VERSION 5.7 ;
  NOWIREEXTENSIONATPIN ON ;
  DIVIDERCHAR "/" ;
  BUSBITCHARS "[]" ;
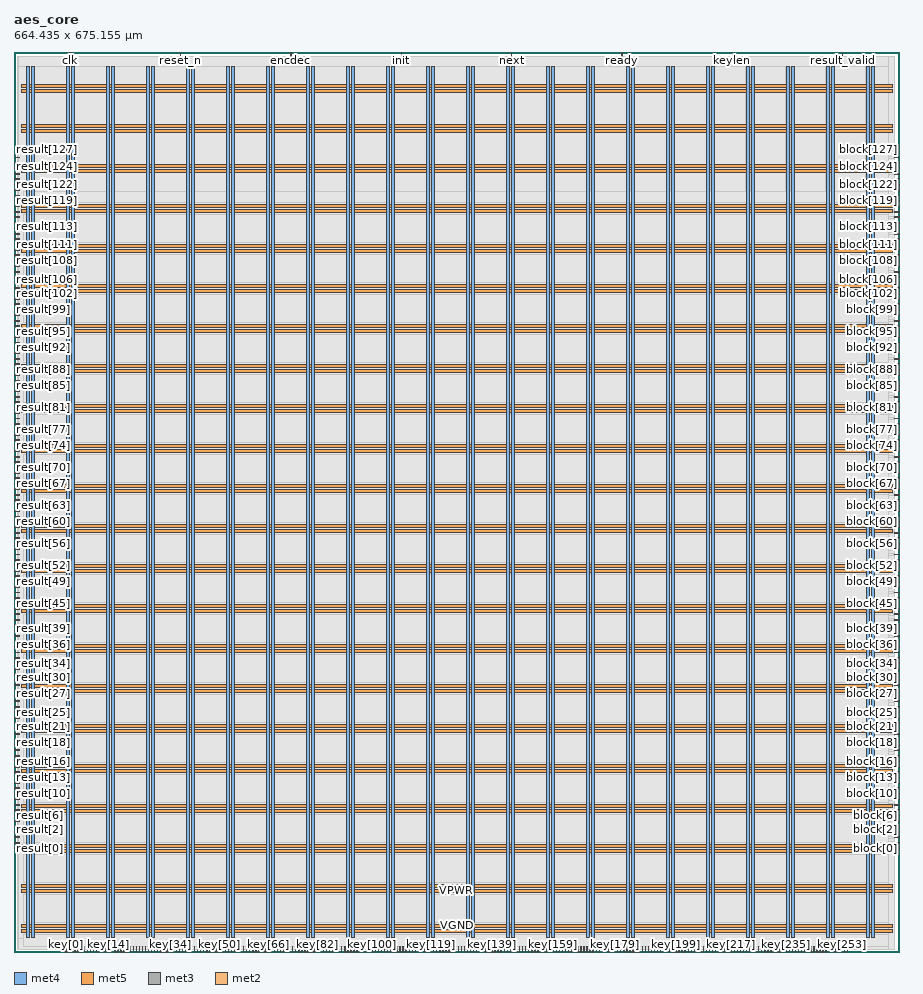
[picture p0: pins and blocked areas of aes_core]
MACRO aes_core
  CLASS BLOCK ;
  FOREIGN aes_core ;
  ORIGIN 0.000 0.000 ;
  SIZE 664.435 BY 675.155 ;
  PIN VGND
    DIRECTION INOUT ;
    USE GROUND ;
    PORT
      LAYER met4 ;
        RECT 13.220 10.640 15.220 663.920 ;
    END
    PORT
      LAYER met4 ;
        RECT 43.220 10.640 45.220 663.920 ;
    END
    PORT
      LAYER met4 ;
        RECT 73.220 10.640 75.220 663.920 ;
    END
    PORT
      LAYER met4 ;
        RECT 103.220 10.640 105.220 663.920 ;
    END
    PORT
      LAYER met4 ;
        RECT 133.220 10.640 135.220 663.920 ;
    END
    PORT
      LAYER met4 ;
        RECT 163.220 10.640 165.220 663.920 ;
    END
    PORT
      LAYER met4 ;
        RECT 193.220 10.640 195.220 663.920 ;
    END
    PORT
      LAYER met4 ;
        RECT 223.220 10.640 225.220 663.920 ;
    END
    PORT
      LAYER met4 ;
        RECT 253.220 10.640 255.220 663.920 ;
    END
    PORT
      LAYER met4 ;
        RECT 283.220 10.640 285.220 663.920 ;
    END
    PORT
      LAYER met4 ;
        RECT 313.220 10.640 315.220 663.920 ;
    END
    PORT
      LAYER met4 ;
        RECT 343.220 10.640 345.220 663.920 ;
    END
    PORT
      LAYER met4 ;
        RECT 373.220 10.640 375.220 663.920 ;
    END
    PORT
      LAYER met4 ;
        RECT 403.220 10.640 405.220 663.920 ;
    END
    PORT
      LAYER met4 ;
        RECT 433.220 10.640 435.220 663.920 ;
    END
    PORT
      LAYER met4 ;
        RECT 463.220 10.640 465.220 663.920 ;
    END
    PORT
      LAYER met4 ;
        RECT 493.220 10.640 495.220 663.920 ;
    END
    PORT
      LAYER met4 ;
        RECT 523.220 10.640 525.220 663.920 ;
    END
    PORT
      LAYER met4 ;
        RECT 553.220 10.640 555.220 663.920 ;
    END
    PORT
      LAYER met4 ;
        RECT 583.220 10.640 585.220 663.920 ;
    END
    PORT
      LAYER met4 ;
        RECT 613.220 10.640 615.220 663.920 ;
    END
    PORT
      LAYER met4 ;
        RECT 643.220 10.640 645.220 663.920 ;
    END
    PORT
      LAYER met5 ;
        RECT 5.280 18.580 658.960 20.580 ;
    END
    PORT
      LAYER met5 ;
        RECT 5.280 48.580 658.960 50.580 ;
    END
    PORT
      LAYER met5 ;
        RECT 5.280 78.580 658.960 80.580 ;
    END
    PORT
      LAYER met5 ;
        RECT 5.280 108.580 658.960 110.580 ;
    END
    PORT
      LAYER met5 ;
        RECT 5.280 138.580 658.960 140.580 ;
    END
    PORT
      LAYER met5 ;
        RECT 5.280 168.580 658.960 170.580 ;
    END
    PORT
      LAYER met5 ;
        RECT 5.280 198.580 658.960 200.580 ;
    END
    PORT
      LAYER met5 ;
        RECT 5.280 228.580 658.960 230.580 ;
    END
    PORT
      LAYER met5 ;
        RECT 5.280 258.580 658.960 260.580 ;
    END
    PORT
      LAYER met5 ;
        RECT 5.280 288.580 658.960 290.580 ;
    END
    PORT
      LAYER met5 ;
        RECT 5.280 318.580 658.960 320.580 ;
    END
    PORT
      LAYER met5 ;
        RECT 5.280 348.580 658.960 350.580 ;
    END
    PORT
      LAYER met5 ;
        RECT 5.280 378.580 658.960 380.580 ;
    END
    PORT
      LAYER met5 ;
        RECT 5.280 408.580 658.960 410.580 ;
    END
    PORT
      LAYER met5 ;
        RECT 5.280 438.580 658.960 440.580 ;
    END
    PORT
      LAYER met5 ;
        RECT 5.280 468.580 658.960 470.580 ;
    END
    PORT
      LAYER met5 ;
        RECT 5.280 498.580 658.960 500.580 ;
    END
    PORT
      LAYER met5 ;
        RECT 5.280 528.580 658.960 530.580 ;
    END
    PORT
      LAYER met5 ;
        RECT 5.280 558.580 658.960 560.580 ;
    END
    PORT
      LAYER met5 ;
        RECT 5.280 588.580 658.960 590.580 ;
    END
    PORT
      LAYER met5 ;
        RECT 5.280 618.580 658.960 620.580 ;
    END
    PORT
      LAYER met5 ;
        RECT 5.280 648.580 658.960 650.580 ;
    END
  END VGND
  PIN VPWR
    DIRECTION INOUT ;
    USE POWER ;
    PORT
      LAYER met4 ;
        RECT 9.520 10.640 11.520 663.920 ;
    END
    PORT
      LAYER met4 ;
        RECT 39.520 10.640 41.520 663.920 ;
    END
    PORT
      LAYER met4 ;
        RECT 69.520 10.640 71.520 663.920 ;
    END
    PORT
      LAYER met4 ;
        RECT 99.520 10.640 101.520 663.920 ;
    END
    PORT
      LAYER met4 ;
        RECT 129.520 10.640 131.520 663.920 ;
    END
    PORT
      LAYER met4 ;
        RECT 159.520 10.640 161.520 663.920 ;
    END
    PORT
      LAYER met4 ;
        RECT 189.520 10.640 191.520 663.920 ;
    END
    PORT
      LAYER met4 ;
        RECT 219.520 10.640 221.520 663.920 ;
    END
    PORT
      LAYER met4 ;
        RECT 249.520 10.640 251.520 663.920 ;
    END
    PORT
      LAYER met4 ;
        RECT 279.520 10.640 281.520 663.920 ;
    END
    PORT
      LAYER met4 ;
        RECT 309.520 10.640 311.520 663.920 ;
    END
    PORT
      LAYER met4 ;
        RECT 339.520 10.640 341.520 663.920 ;
    END
    PORT
      LAYER met4 ;
        RECT 369.520 10.640 371.520 663.920 ;
    END
    PORT
      LAYER met4 ;
        RECT 399.520 10.640 401.520 663.920 ;
    END
    PORT
      LAYER met4 ;
        RECT 429.520 10.640 431.520 663.920 ;
    END
    PORT
      LAYER met4 ;
        RECT 459.520 10.640 461.520 663.920 ;
    END
    PORT
      LAYER met4 ;
        RECT 489.520 10.640 491.520 663.920 ;
    END
    PORT
      LAYER met4 ;
        RECT 519.520 10.640 521.520 663.920 ;
    END
    PORT
      LAYER met4 ;
        RECT 549.520 10.640 551.520 663.920 ;
    END
    PORT
      LAYER met4 ;
        RECT 579.520 10.640 581.520 663.920 ;
    END
    PORT
      LAYER met4 ;
        RECT 609.520 10.640 611.520 663.920 ;
    END
    PORT
      LAYER met4 ;
        RECT 639.520 10.640 641.520 663.920 ;
    END
    PORT
      LAYER met5 ;
        RECT 5.280 14.880 658.960 16.880 ;
    END
    PORT
      LAYER met5 ;
        RECT 5.280 44.880 658.960 46.880 ;
    END
    PORT
      LAYER met5 ;
        RECT 5.280 74.880 658.960 76.880 ;
    END
    PORT
      LAYER met5 ;
        RECT 5.280 104.880 658.960 106.880 ;
    END
    PORT
      LAYER met5 ;
        RECT 5.280 134.880 658.960 136.880 ;
    END
    PORT
      LAYER met5 ;
        RECT 5.280 164.880 658.960 166.880 ;
    END
    PORT
      LAYER met5 ;
        RECT 5.280 194.880 658.960 196.880 ;
    END
    PORT
      LAYER met5 ;
        RECT 5.280 224.880 658.960 226.880 ;
    END
    PORT
      LAYER met5 ;
        RECT 5.280 254.880 658.960 256.880 ;
    END
    PORT
      LAYER met5 ;
        RECT 5.280 284.880 658.960 286.880 ;
    END
    PORT
      LAYER met5 ;
        RECT 5.280 314.880 658.960 316.880 ;
    END
    PORT
      LAYER met5 ;
        RECT 5.280 344.880 658.960 346.880 ;
    END
    PORT
      LAYER met5 ;
        RECT 5.280 374.880 658.960 376.880 ;
    END
    PORT
      LAYER met5 ;
        RECT 5.280 404.880 658.960 406.880 ;
    END
    PORT
      LAYER met5 ;
        RECT 5.280 434.880 658.960 436.880 ;
    END
    PORT
      LAYER met5 ;
        RECT 5.280 464.880 658.960 466.880 ;
    END
    PORT
      LAYER met5 ;
        RECT 5.280 494.880 658.960 496.880 ;
    END
    PORT
      LAYER met5 ;
        RECT 5.280 524.880 658.960 526.880 ;
    END
    PORT
      LAYER met5 ;
        RECT 5.280 554.880 658.960 556.880 ;
    END
    PORT
      LAYER met5 ;
        RECT 5.280 584.880 658.960 586.880 ;
    END
    PORT
      LAYER met5 ;
        RECT 5.280 614.880 658.960 616.880 ;
    END
    PORT
      LAYER met5 ;
        RECT 5.280 644.880 658.960 646.880 ;
    END
  END VPWR
  PIN block[0]
    DIRECTION INPUT ;
    USE SIGNAL ;
    ANTENNAGATEAREA 0.247500 ;
    PORT
      LAYER met3 ;
        RECT 660.435 77.560 664.435 78.160 ;
    END
  END block[0]
  PIN block[100]
    DIRECTION INPUT ;
    USE SIGNAL ;
    ANTENNAGATEAREA 0.213000 ;
    PORT
      LAYER met3 ;
        RECT 660.435 485.560 664.435 486.160 ;
    END
  END block[100]
  PIN block[101]
    DIRECTION INPUT ;
    USE SIGNAL ;
    ANTENNAGATEAREA 0.213000 ;
    PORT
      LAYER met3 ;
        RECT 660.435 489.640 664.435 490.240 ;
    END
  END block[101]
  PIN block[102]
    DIRECTION INPUT ;
    USE SIGNAL ;
    ANTENNAGATEAREA 0.213000 ;
    PORT
      LAYER met3 ;
        RECT 660.435 493.720 664.435 494.320 ;
    END
  END block[102]
  PIN block[103]
    DIRECTION INPUT ;
    USE SIGNAL ;
    ANTENNAGATEAREA 0.159000 ;
    PORT
      LAYER met3 ;
        RECT 660.435 497.800 664.435 498.400 ;
    END
  END block[103]
  PIN block[104]
    DIRECTION INPUT ;
    USE SIGNAL ;
    ANTENNAGATEAREA 0.213000 ;
    PORT
      LAYER met3 ;
        RECT 660.435 501.880 664.435 502.480 ;
    END
  END block[104]
  PIN block[105]
    DIRECTION INPUT ;
    USE SIGNAL ;
    ANTENNAGATEAREA 0.213000 ;
    PORT
      LAYER met3 ;
        RECT 660.435 505.960 664.435 506.560 ;
    END
  END block[105]
  PIN block[106]
    DIRECTION INPUT ;
    USE SIGNAL ;
    ANTENNAGATEAREA 0.213000 ;
    PORT
      LAYER met3 ;
        RECT 660.435 510.040 664.435 510.640 ;
    END
  END block[106]
  PIN block[107]
    DIRECTION INPUT ;
    USE SIGNAL ;
    ANTENNAGATEAREA 0.213000 ;
    PORT
      LAYER met3 ;
        RECT 660.435 514.120 664.435 514.720 ;
    END
  END block[107]
  PIN block[108]
    DIRECTION INPUT ;
    USE SIGNAL ;
    ANTENNAGATEAREA 0.213000 ;
    PORT
      LAYER met3 ;
        RECT 660.435 518.200 664.435 518.800 ;
    END
  END block[108]
  PIN block[109]
    DIRECTION INPUT ;
    USE SIGNAL ;
    ANTENNAGATEAREA 0.213000 ;
    PORT
      LAYER met3 ;
        RECT 660.435 522.280 664.435 522.880 ;
    END
  END block[109]
  PIN block[10]
    DIRECTION INPUT ;
    USE SIGNAL ;
    ANTENNAGATEAREA 0.213000 ;
    PORT
      LAYER met3 ;
        RECT 660.435 118.360 664.435 118.960 ;
    END
  END block[10]
  PIN block[110]
    DIRECTION INPUT ;
    USE SIGNAL ;
    ANTENNAGATEAREA 0.159000 ;
    PORT
      LAYER met3 ;
        RECT 660.435 526.360 664.435 526.960 ;
    END
  END block[110]
  PIN block[111]
    DIRECTION INPUT ;
    USE SIGNAL ;
    ANTENNAGATEAREA 0.213000 ;
    PORT
      LAYER met3 ;
        RECT 660.435 530.440 664.435 531.040 ;
    END
  END block[111]
  PIN block[112]
    DIRECTION INPUT ;
    USE SIGNAL ;
    ANTENNAGATEAREA 0.159000 ;
    PORT
      LAYER met3 ;
        RECT 660.435 534.520 664.435 535.120 ;
    END
  END block[112]
  PIN block[113]
    DIRECTION INPUT ;
    USE SIGNAL ;
    ANTENNAGATEAREA 0.213000 ;
    PORT
      LAYER met3 ;
        RECT 660.435 538.600 664.435 539.200 ;
    END
  END block[113]
  PIN block[114]
    DIRECTION INPUT ;
    USE SIGNAL ;
    ANTENNAGATEAREA 0.213000 ;
    PORT
      LAYER met3 ;
        RECT 660.435 542.680 664.435 543.280 ;
    END
  END block[114]
  PIN block[115]
    DIRECTION INPUT ;
    USE SIGNAL ;
    ANTENNAGATEAREA 0.213000 ;
    PORT
      LAYER met3 ;
        RECT 660.435 546.760 664.435 547.360 ;
    END
  END block[115]
  PIN block[116]
    DIRECTION INPUT ;
    USE SIGNAL ;
    ANTENNAGATEAREA 0.213000 ;
    PORT
      LAYER met3 ;
        RECT 660.435 550.840 664.435 551.440 ;
    END
  END block[116]
  PIN block[117]
    DIRECTION INPUT ;
    USE SIGNAL ;
    ANTENNAGATEAREA 0.247500 ;
    PORT
      LAYER met3 ;
        RECT 660.435 554.920 664.435 555.520 ;
    END
  END block[117]
  PIN block[118]
    DIRECTION INPUT ;
    USE SIGNAL ;
    ANTENNAGATEAREA 0.213000 ;
    PORT
      LAYER met3 ;
        RECT 660.435 559.000 664.435 559.600 ;
    END
  END block[118]
  PIN block[119]
    DIRECTION INPUT ;
    USE SIGNAL ;
    ANTENNAGATEAREA 0.213000 ;
    PORT
      LAYER met3 ;
        RECT 660.435 563.080 664.435 563.680 ;
    END
  END block[119]
  PIN block[11]
    DIRECTION INPUT ;
    USE SIGNAL ;
    ANTENNAGATEAREA 0.247500 ;
    PORT
      LAYER met3 ;
        RECT 660.435 122.440 664.435 123.040 ;
    END
  END block[11]
  PIN block[120]
    DIRECTION INPUT ;
    USE SIGNAL ;
    ANTENNAGATEAREA 0.213000 ;
    PORT
      LAYER met3 ;
        RECT 660.435 567.160 664.435 567.760 ;
    END
  END block[120]
  PIN block[121]
    DIRECTION INPUT ;
    USE SIGNAL ;
    ANTENNAGATEAREA 0.213000 ;
    PORT
      LAYER met3 ;
        RECT 660.435 571.240 664.435 571.840 ;
    END
  END block[121]
  PIN block[122]
    DIRECTION INPUT ;
    USE SIGNAL ;
    ANTENNAGATEAREA 0.213000 ;
    PORT
      LAYER met3 ;
        RECT 660.435 575.320 664.435 575.920 ;
    END
  END block[122]
  PIN block[123]
    DIRECTION INPUT ;
    USE SIGNAL ;
    ANTENNAGATEAREA 0.213000 ;
    PORT
      LAYER met3 ;
        RECT 660.435 579.400 664.435 580.000 ;
    END
  END block[123]
  PIN block[124]
    DIRECTION INPUT ;
    USE SIGNAL ;
    ANTENNAGATEAREA 0.213000 ;
    PORT
      LAYER met3 ;
        RECT 660.435 583.480 664.435 584.080 ;
    END
  END block[124]
  PIN block[125]
    DIRECTION INPUT ;
    USE SIGNAL ;
    ANTENNAGATEAREA 0.213000 ;
    PORT
      LAYER met3 ;
        RECT 660.435 587.560 664.435 588.160 ;
    END
  END block[125]
  PIN block[126]
    DIRECTION INPUT ;
    USE SIGNAL ;
    ANTENNAGATEAREA 0.213000 ;
    PORT
      LAYER met3 ;
        RECT 660.435 591.640 664.435 592.240 ;
    END
  END block[126]
  PIN block[127]
    DIRECTION INPUT ;
    USE SIGNAL ;
    ANTENNAGATEAREA 0.213000 ;
    PORT
      LAYER met3 ;
        RECT 660.435 595.720 664.435 596.320 ;
    END
  END block[127]
  PIN block[12]
    DIRECTION INPUT ;
    USE SIGNAL ;
    ANTENNAGATEAREA 0.247500 ;
    PORT
      LAYER met3 ;
        RECT 660.435 126.520 664.435 127.120 ;
    END
  END block[12]
  PIN block[13]
    DIRECTION INPUT ;
    USE SIGNAL ;
    ANTENNAGATEAREA 0.247500 ;
    PORT
      LAYER met3 ;
        RECT 660.435 130.600 664.435 131.200 ;
    END
  END block[13]
  PIN block[14]
    DIRECTION INPUT ;
    USE SIGNAL ;
    ANTENNAGATEAREA 0.247500 ;
    PORT
      LAYER met3 ;
        RECT 660.435 134.680 664.435 135.280 ;
    END
  END block[14]
  PIN block[15]
    DIRECTION INPUT ;
    USE SIGNAL ;
    ANTENNAGATEAREA 0.247500 ;
    PORT
      LAYER met3 ;
        RECT 660.435 138.760 664.435 139.360 ;
    END
  END block[15]
  PIN block[16]
    DIRECTION INPUT ;
    USE SIGNAL ;
    ANTENNAGATEAREA 0.213000 ;
    PORT
      LAYER met3 ;
        RECT 660.435 142.840 664.435 143.440 ;
    END
  END block[16]
  PIN block[17]
    DIRECTION INPUT ;
    USE SIGNAL ;
    ANTENNAGATEAREA 0.213000 ;
    PORT
      LAYER met3 ;
        RECT 660.435 146.920 664.435 147.520 ;
    END
  END block[17]
  PIN block[18]
    DIRECTION INPUT ;
    USE SIGNAL ;
    ANTENNAGATEAREA 0.213000 ;
    PORT
      LAYER met3 ;
        RECT 660.435 151.000 664.435 151.600 ;
    END
  END block[18]
  PIN block[19]
    DIRECTION INPUT ;
    USE SIGNAL ;
    ANTENNAGATEAREA 0.247500 ;
    PORT
      LAYER met3 ;
        RECT 660.435 155.080 664.435 155.680 ;
    END
  END block[19]
  PIN block[1]
    DIRECTION INPUT ;
    USE SIGNAL ;
    ANTENNAGATEAREA 0.247500 ;
    PORT
      LAYER met3 ;
        RECT 660.435 81.640 664.435 82.240 ;
    END
  END block[1]
  PIN block[20]
    DIRECTION INPUT ;
    USE SIGNAL ;
    ANTENNAGATEAREA 0.247500 ;
    PORT
      LAYER met3 ;
        RECT 660.435 159.160 664.435 159.760 ;
    END
  END block[20]
  PIN block[21]
    DIRECTION INPUT ;
    USE SIGNAL ;
    ANTENNAGATEAREA 0.247500 ;
    PORT
      LAYER met3 ;
        RECT 660.435 163.240 664.435 163.840 ;
    END
  END block[21]
  PIN block[22]
    DIRECTION INPUT ;
    USE SIGNAL ;
    ANTENNAGATEAREA 0.247500 ;
    PORT
      LAYER met3 ;
        RECT 660.435 167.320 664.435 167.920 ;
    END
  END block[22]
  PIN block[23]
    DIRECTION INPUT ;
    USE SIGNAL ;
    ANTENNAGATEAREA 0.213000 ;
    PORT
      LAYER met3 ;
        RECT 660.435 171.400 664.435 172.000 ;
    END
  END block[23]
  PIN block[24]
    DIRECTION INPUT ;
    USE SIGNAL ;
    ANTENNAGATEAREA 0.213000 ;
    PORT
      LAYER met3 ;
        RECT 660.435 175.480 664.435 176.080 ;
    END
  END block[24]
  PIN block[25]
    DIRECTION INPUT ;
    USE SIGNAL ;
    ANTENNAGATEAREA 0.213000 ;
    PORT
      LAYER met3 ;
        RECT 660.435 179.560 664.435 180.160 ;
    END
  END block[25]
  PIN block[26]
    DIRECTION INPUT ;
    USE SIGNAL ;
    ANTENNAGATEAREA 0.213000 ;
    PORT
      LAYER met3 ;
        RECT 660.435 183.640 664.435 184.240 ;
    END
  END block[26]
  PIN block[27]
    DIRECTION INPUT ;
    USE SIGNAL ;
    ANTENNAGATEAREA 0.247500 ;
    PORT
      LAYER met3 ;
        RECT 660.435 187.720 664.435 188.320 ;
    END
  END block[27]
  PIN block[28]
    DIRECTION INPUT ;
    USE SIGNAL ;
    ANTENNAGATEAREA 0.247500 ;
    PORT
      LAYER met3 ;
        RECT 660.435 191.800 664.435 192.400 ;
    END
  END block[28]
  PIN block[29]
    DIRECTION INPUT ;
    USE SIGNAL ;
    ANTENNAGATEAREA 0.247500 ;
    PORT
      LAYER met3 ;
        RECT 660.435 195.880 664.435 196.480 ;
    END
  END block[29]
  PIN block[2]
    DIRECTION INPUT ;
    USE SIGNAL ;
    ANTENNAGATEAREA 0.247500 ;
    PORT
      LAYER met3 ;
        RECT 660.435 85.720 664.435 86.320 ;
    END
  END block[2]
  PIN block[30]
    DIRECTION INPUT ;
    USE SIGNAL ;
    ANTENNAGATEAREA 0.213000 ;
    PORT
      LAYER met3 ;
        RECT 660.435 199.960 664.435 200.560 ;
    END
  END block[30]
  PIN block[31]
    DIRECTION INPUT ;
    USE SIGNAL ;
    ANTENNAGATEAREA 0.213000 ;
    PORT
      LAYER met3 ;
        RECT 660.435 204.040 664.435 204.640 ;
    END
  END block[31]
  PIN block[32]
    DIRECTION INPUT ;
    USE SIGNAL ;
    ANTENNAGATEAREA 0.213000 ;
    PORT
      LAYER met3 ;
        RECT 660.435 208.120 664.435 208.720 ;
    END
  END block[32]
  PIN block[33]
    DIRECTION INPUT ;
    USE SIGNAL ;
    ANTENNAGATEAREA 0.213000 ;
    PORT
      LAYER met3 ;
        RECT 660.435 212.200 664.435 212.800 ;
    END
  END block[33]
  PIN block[34]
    DIRECTION INPUT ;
    USE SIGNAL ;
    ANTENNAGATEAREA 0.213000 ;
    PORT
      LAYER met3 ;
        RECT 660.435 216.280 664.435 216.880 ;
    END
  END block[34]
  PIN block[35]
    DIRECTION INPUT ;
    USE SIGNAL ;
    ANTENNAGATEAREA 0.213000 ;
    PORT
      LAYER met3 ;
        RECT 660.435 220.360 664.435 220.960 ;
    END
  END block[35]
  PIN block[36]
    DIRECTION INPUT ;
    USE SIGNAL ;
    ANTENNAGATEAREA 0.213000 ;
    PORT
      LAYER met3 ;
        RECT 660.435 224.440 664.435 225.040 ;
    END
  END block[36]
  PIN block[37]
    DIRECTION INPUT ;
    USE SIGNAL ;
    ANTENNAGATEAREA 0.247500 ;
    PORT
      LAYER met3 ;
        RECT 660.435 228.520 664.435 229.120 ;
    END
  END block[37]
  PIN block[38]
    DIRECTION INPUT ;
    USE SIGNAL ;
    ANTENNAGATEAREA 0.213000 ;
    PORT
      LAYER met3 ;
        RECT 660.435 232.600 664.435 233.200 ;
    END
  END block[38]
  PIN block[39]
    DIRECTION INPUT ;
    USE SIGNAL ;
    ANTENNAGATEAREA 0.159000 ;
    PORT
      LAYER met3 ;
        RECT 660.435 236.680 664.435 237.280 ;
    END
  END block[39]
  PIN block[3]
    DIRECTION INPUT ;
    USE SIGNAL ;
    ANTENNAGATEAREA 0.247500 ;
    PORT
      LAYER met3 ;
        RECT 660.435 89.800 664.435 90.400 ;
    END
  END block[3]
  PIN block[40]
    DIRECTION INPUT ;
    USE SIGNAL ;
    ANTENNAGATEAREA 0.159000 ;
    PORT
      LAYER met3 ;
        RECT 660.435 240.760 664.435 241.360 ;
    END
  END block[40]
  PIN block[41]
    DIRECTION INPUT ;
    USE SIGNAL ;
    ANTENNAGATEAREA 0.213000 ;
    PORT
      LAYER met3 ;
        RECT 660.435 244.840 664.435 245.440 ;
    END
  END block[41]
  PIN block[42]
    DIRECTION INPUT ;
    USE SIGNAL ;
    ANTENNAGATEAREA 0.213000 ;
    PORT
      LAYER met3 ;
        RECT 660.435 248.920 664.435 249.520 ;
    END
  END block[42]
  PIN block[43]
    DIRECTION INPUT ;
    USE SIGNAL ;
    ANTENNAGATEAREA 0.159000 ;
    PORT
      LAYER met3 ;
        RECT 660.435 253.000 664.435 253.600 ;
    END
  END block[43]
  PIN block[44]
    DIRECTION INPUT ;
    USE SIGNAL ;
    ANTENNAGATEAREA 0.213000 ;
    PORT
      LAYER met3 ;
        RECT 660.435 257.080 664.435 257.680 ;
    END
  END block[44]
  PIN block[45]
    DIRECTION INPUT ;
    USE SIGNAL ;
    ANTENNAGATEAREA 0.213000 ;
    PORT
      LAYER met3 ;
        RECT 660.435 261.160 664.435 261.760 ;
    END
  END block[45]
  PIN block[46]
    DIRECTION INPUT ;
    USE SIGNAL ;
    ANTENNAGATEAREA 0.213000 ;
    PORT
      LAYER met3 ;
        RECT 660.435 265.240 664.435 265.840 ;
    END
  END block[46]
  PIN block[47]
    DIRECTION INPUT ;
    USE SIGNAL ;
    ANTENNAGATEAREA 0.213000 ;
    PORT
      LAYER met3 ;
        RECT 660.435 269.320 664.435 269.920 ;
    END
  END block[47]
  PIN block[48]
    DIRECTION INPUT ;
    USE SIGNAL ;
    ANTENNAGATEAREA 0.159000 ;
    PORT
      LAYER met3 ;
        RECT 660.435 273.400 664.435 274.000 ;
    END
  END block[48]
  PIN block[49]
    DIRECTION INPUT ;
    USE SIGNAL ;
    ANTENNAGATEAREA 0.213000 ;
    PORT
      LAYER met3 ;
        RECT 660.435 277.480 664.435 278.080 ;
    END
  END block[49]
  PIN block[4]
    DIRECTION INPUT ;
    USE SIGNAL ;
    ANTENNAGATEAREA 0.247500 ;
    PORT
      LAYER met3 ;
        RECT 660.435 93.880 664.435 94.480 ;
    END
  END block[4]
  PIN block[50]
    DIRECTION INPUT ;
    USE SIGNAL ;
    ANTENNAGATEAREA 0.159000 ;
    PORT
      LAYER met3 ;
        RECT 660.435 281.560 664.435 282.160 ;
    END
  END block[50]
  PIN block[51]
    DIRECTION INPUT ;
    USE SIGNAL ;
    ANTENNAGATEAREA 0.159000 ;
    PORT
      LAYER met3 ;
        RECT 660.435 285.640 664.435 286.240 ;
    END
  END block[51]
  PIN block[52]
    DIRECTION INPUT ;
    USE SIGNAL ;
    ANTENNAGATEAREA 0.213000 ;
    PORT
      LAYER met3 ;
        RECT 660.435 289.720 664.435 290.320 ;
    END
  END block[52]
  PIN block[53]
    DIRECTION INPUT ;
    USE SIGNAL ;
    ANTENNAGATEAREA 0.213000 ;
    PORT
      LAYER met3 ;
        RECT 660.435 293.800 664.435 294.400 ;
    END
  END block[53]
  PIN block[54]
    DIRECTION INPUT ;
    USE SIGNAL ;
    ANTENNAGATEAREA 0.213000 ;
    PORT
      LAYER met3 ;
        RECT 660.435 297.880 664.435 298.480 ;
    END
  END block[54]
  PIN block[55]
    DIRECTION INPUT ;
    USE SIGNAL ;
    ANTENNAGATEAREA 0.159000 ;
    PORT
      LAYER met3 ;
        RECT 660.435 301.960 664.435 302.560 ;
    END
  END block[55]
  PIN block[56]
    DIRECTION INPUT ;
    USE SIGNAL ;
    ANTENNAGATEAREA 0.159000 ;
    PORT
      LAYER met3 ;
        RECT 660.435 306.040 664.435 306.640 ;
    END
  END block[56]
  PIN block[57]
    DIRECTION INPUT ;
    USE SIGNAL ;
    ANTENNAGATEAREA 0.159000 ;
    PORT
      LAYER met3 ;
        RECT 660.435 310.120 664.435 310.720 ;
    END
  END block[57]
  PIN block[58]
    DIRECTION INPUT ;
    USE SIGNAL ;
    ANTENNAGATEAREA 0.159000 ;
    PORT
      LAYER met3 ;
        RECT 660.435 314.200 664.435 314.800 ;
    END
  END block[58]
  PIN block[59]
    DIRECTION INPUT ;
    USE SIGNAL ;
    ANTENNAGATEAREA 0.213000 ;
    PORT
      LAYER met3 ;
        RECT 660.435 318.280 664.435 318.880 ;
    END
  END block[59]
  PIN block[5]
    DIRECTION INPUT ;
    USE SIGNAL ;
    ANTENNAGATEAREA 0.247500 ;
    PORT
      LAYER met3 ;
        RECT 660.435 97.960 664.435 98.560 ;
    END
  END block[5]
  PIN block[60]
    DIRECTION INPUT ;
    USE SIGNAL ;
    ANTENNAGATEAREA 0.213000 ;
    PORT
      LAYER met3 ;
        RECT 660.435 322.360 664.435 322.960 ;
    END
  END block[60]
  PIN block[61]
    DIRECTION INPUT ;
    USE SIGNAL ;
    ANTENNAGATEAREA 0.213000 ;
    PORT
      LAYER met3 ;
        RECT 660.435 326.440 664.435 327.040 ;
    END
  END block[61]
  PIN block[62]
    DIRECTION INPUT ;
    USE SIGNAL ;
    ANTENNAGATEAREA 0.159000 ;
    PORT
      LAYER met3 ;
        RECT 660.435 330.520 664.435 331.120 ;
    END
  END block[62]
  PIN block[63]
    DIRECTION INPUT ;
    USE SIGNAL ;
    ANTENNAGATEAREA 0.159000 ;
    PORT
      LAYER met3 ;
        RECT 660.435 334.600 664.435 335.200 ;
    END
  END block[63]
  PIN block[64]
    DIRECTION INPUT ;
    USE SIGNAL ;
    ANTENNAGATEAREA 0.213000 ;
    PORT
      LAYER met3 ;
        RECT 660.435 338.680 664.435 339.280 ;
    END
  END block[64]
  PIN block[65]
    DIRECTION INPUT ;
    USE SIGNAL ;
    ANTENNAGATEAREA 0.213000 ;
    PORT
      LAYER met3 ;
        RECT 660.435 342.760 664.435 343.360 ;
    END
  END block[65]
  PIN block[66]
    DIRECTION INPUT ;
    USE SIGNAL ;
    ANTENNAGATEAREA 0.159000 ;
    PORT
      LAYER met3 ;
        RECT 660.435 346.840 664.435 347.440 ;
    END
  END block[66]
  PIN block[67]
    DIRECTION INPUT ;
    USE SIGNAL ;
    ANTENNAGATEAREA 0.213000 ;
    PORT
      LAYER met3 ;
        RECT 660.435 350.920 664.435 351.520 ;
    END
  END block[67]
  PIN block[68]
    DIRECTION INPUT ;
    USE SIGNAL ;
    ANTENNAGATEAREA 0.213000 ;
    PORT
      LAYER met3 ;
        RECT 660.435 355.000 664.435 355.600 ;
    END
  END block[68]
  PIN block[69]
    DIRECTION INPUT ;
    USE SIGNAL ;
    ANTENNAGATEAREA 0.213000 ;
    PORT
      LAYER met3 ;
        RECT 660.435 359.080 664.435 359.680 ;
    END
  END block[69]
  PIN block[6]
    DIRECTION INPUT ;
    USE SIGNAL ;
    ANTENNAGATEAREA 0.247500 ;
    PORT
      LAYER met3 ;
        RECT 660.435 102.040 664.435 102.640 ;
    END
  END block[6]
  PIN block[70]
    DIRECTION INPUT ;
    USE SIGNAL ;
    ANTENNAGATEAREA 0.213000 ;
    PORT
      LAYER met3 ;
        RECT 660.435 363.160 664.435 363.760 ;
    END
  END block[70]
  PIN block[71]
    DIRECTION INPUT ;
    USE SIGNAL ;
    ANTENNAGATEAREA 0.213000 ;
    PORT
      LAYER met3 ;
        RECT 660.435 367.240 664.435 367.840 ;
    END
  END block[71]
  PIN block[72]
    DIRECTION INPUT ;
    USE SIGNAL ;
    ANTENNAGATEAREA 0.213000 ;
    PORT
      LAYER met3 ;
        RECT 660.435 371.320 664.435 371.920 ;
    END
  END block[72]
  PIN block[73]
    DIRECTION INPUT ;
    USE SIGNAL ;
    ANTENNAGATEAREA 0.213000 ;
    PORT
      LAYER met3 ;
        RECT 660.435 375.400 664.435 376.000 ;
    END
  END block[73]
  PIN block[74]
    DIRECTION INPUT ;
    USE SIGNAL ;
    ANTENNAGATEAREA 0.213000 ;
    PORT
      LAYER met3 ;
        RECT 660.435 379.480 664.435 380.080 ;
    END
  END block[74]
  PIN block[75]
    DIRECTION INPUT ;
    USE SIGNAL ;
    ANTENNAGATEAREA 0.247500 ;
    PORT
      LAYER met3 ;
        RECT 660.435 383.560 664.435 384.160 ;
    END
  END block[75]
  PIN block[76]
    DIRECTION INPUT ;
    USE SIGNAL ;
    ANTENNAGATEAREA 0.213000 ;
    PORT
      LAYER met3 ;
        RECT 660.435 387.640 664.435 388.240 ;
    END
  END block[76]
  PIN block[77]
    DIRECTION INPUT ;
    USE SIGNAL ;
    ANTENNAGATEAREA 0.213000 ;
    PORT
      LAYER met3 ;
        RECT 660.435 391.720 664.435 392.320 ;
    END
  END block[77]
  PIN block[78]
    DIRECTION INPUT ;
    USE SIGNAL ;
    ANTENNAGATEAREA 0.159000 ;
    PORT
      LAYER met3 ;
        RECT 660.435 395.800 664.435 396.400 ;
    END
  END block[78]
  PIN block[79]
    DIRECTION INPUT ;
    USE SIGNAL ;
    ANTENNAGATEAREA 0.159000 ;
    PORT
      LAYER met3 ;
        RECT 660.435 399.880 664.435 400.480 ;
    END
  END block[79]
  PIN block[7]
    DIRECTION INPUT ;
    USE SIGNAL ;
    ANTENNAGATEAREA 0.213000 ;
    PORT
      LAYER met3 ;
        RECT 660.435 106.120 664.435 106.720 ;
    END
  END block[7]
  PIN block[80]
    DIRECTION INPUT ;
    USE SIGNAL ;
    ANTENNAGATEAREA 0.159000 ;
    PORT
      LAYER met3 ;
        RECT 660.435 403.960 664.435 404.560 ;
    END
  END block[80]
  PIN block[81]
    DIRECTION INPUT ;
    USE SIGNAL ;
    ANTENNAGATEAREA 0.213000 ;
    PORT
      LAYER met3 ;
        RECT 660.435 408.040 664.435 408.640 ;
    END
  END block[81]
  PIN block[82]
    DIRECTION INPUT ;
    USE SIGNAL ;
    ANTENNAGATEAREA 0.159000 ;
    PORT
      LAYER met3 ;
        RECT 660.435 412.120 664.435 412.720 ;
    END
  END block[82]
  PIN block[83]
    DIRECTION INPUT ;
    USE SIGNAL ;
    ANTENNAGATEAREA 0.159000 ;
    PORT
      LAYER met3 ;
        RECT 660.435 416.200 664.435 416.800 ;
    END
  END block[83]
  PIN block[84]
    DIRECTION INPUT ;
    USE SIGNAL ;
    ANTENNAGATEAREA 0.159000 ;
    PORT
      LAYER met3 ;
        RECT 660.435 420.280 664.435 420.880 ;
    END
  END block[84]
  PIN block[85]
    DIRECTION INPUT ;
    USE SIGNAL ;
    ANTENNAGATEAREA 0.213000 ;
    PORT
      LAYER met3 ;
        RECT 660.435 424.360 664.435 424.960 ;
    END
  END block[85]
  PIN block[86]
    DIRECTION INPUT ;
    USE SIGNAL ;
    ANTENNAGATEAREA 0.213000 ;
    PORT
      LAYER met3 ;
        RECT 660.435 428.440 664.435 429.040 ;
    END
  END block[86]
  PIN block[87]
    DIRECTION INPUT ;
    USE SIGNAL ;
    ANTENNAGATEAREA 0.159000 ;
    PORT
      LAYER met3 ;
        RECT 660.435 432.520 664.435 433.120 ;
    END
  END block[87]
  PIN block[88]
    DIRECTION INPUT ;
    USE SIGNAL ;
    ANTENNAGATEAREA 0.159000 ;
    PORT
      LAYER met3 ;
        RECT 660.435 436.600 664.435 437.200 ;
    END
  END block[88]
  PIN block[89]
    DIRECTION INPUT ;
    USE SIGNAL ;
    ANTENNAGATEAREA 0.213000 ;
    PORT
      LAYER met3 ;
        RECT 660.435 440.680 664.435 441.280 ;
    END
  END block[89]
  PIN block[8]
    DIRECTION INPUT ;
    USE SIGNAL ;
    ANTENNAGATEAREA 0.247500 ;
    PORT
      LAYER met3 ;
        RECT 660.435 110.200 664.435 110.800 ;
    END
  END block[8]
  PIN block[90]
    DIRECTION INPUT ;
    USE SIGNAL ;
    ANTENNAGATEAREA 0.213000 ;
    PORT
      LAYER met3 ;
        RECT 660.435 444.760 664.435 445.360 ;
    END
  END block[90]
  PIN block[91]
    DIRECTION INPUT ;
    USE SIGNAL ;
    ANTENNAGATEAREA 0.213000 ;
    PORT
      LAYER met3 ;
        RECT 660.435 448.840 664.435 449.440 ;
    END
  END block[91]
  PIN block[92]
    DIRECTION INPUT ;
    USE SIGNAL ;
    ANTENNAGATEAREA 0.213000 ;
    PORT
      LAYER met3 ;
        RECT 660.435 452.920 664.435 453.520 ;
    END
  END block[92]
  PIN block[93]
    DIRECTION INPUT ;
    USE SIGNAL ;
    ANTENNAGATEAREA 0.213000 ;
    PORT
      LAYER met3 ;
        RECT 660.435 457.000 664.435 457.600 ;
    END
  END block[93]
  PIN block[94]
    DIRECTION INPUT ;
    USE SIGNAL ;
    ANTENNAGATEAREA 0.213000 ;
    PORT
      LAYER met3 ;
        RECT 660.435 461.080 664.435 461.680 ;
    END
  END block[94]
  PIN block[95]
    DIRECTION INPUT ;
    USE SIGNAL ;
    ANTENNAGATEAREA 0.213000 ;
    PORT
      LAYER met3 ;
        RECT 660.435 465.160 664.435 465.760 ;
    END
  END block[95]
  PIN block[96]
    DIRECTION INPUT ;
    USE SIGNAL ;
    ANTENNAGATEAREA 0.213000 ;
    PORT
      LAYER met3 ;
        RECT 660.435 469.240 664.435 469.840 ;
    END
  END block[96]
  PIN block[97]
    DIRECTION INPUT ;
    USE SIGNAL ;
    ANTENNAGATEAREA 0.213000 ;
    PORT
      LAYER met3 ;
        RECT 660.435 473.320 664.435 473.920 ;
    END
  END block[97]
  PIN block[98]
    DIRECTION INPUT ;
    USE SIGNAL ;
    ANTENNAGATEAREA 0.159000 ;
    PORT
      LAYER met3 ;
        RECT 660.435 477.400 664.435 478.000 ;
    END
  END block[98]
  PIN block[99]
    DIRECTION INPUT ;
    USE SIGNAL ;
    ANTENNAGATEAREA 0.213000 ;
    PORT
      LAYER met3 ;
        RECT 660.435 481.480 664.435 482.080 ;
    END
  END block[99]
  PIN block[9]
    DIRECTION INPUT ;
    USE SIGNAL ;
    ANTENNAGATEAREA 0.247500 ;
    PORT
      LAYER met3 ;
        RECT 660.435 114.280 664.435 114.880 ;
    END
  END block[9]
  PIN clk
    DIRECTION INPUT ;
    USE SIGNAL ;
    ANTENNAGATEAREA 1.286700 ;
    ANTENNADIFFAREA 0.434700 ;
    PORT
      LAYER met2 ;
        RECT 41.950 671.155 42.230 675.155 ;
    END
  END clk
  PIN encdec
    DIRECTION INPUT ;
    USE SIGNAL ;
    ANTENNAGATEAREA 0.852000 ;
    PORT
      LAYER met2 ;
        RECT 207.550 671.155 207.830 675.155 ;
    END
  END encdec
  PIN init
    DIRECTION INPUT ;
    USE SIGNAL ;
    ANTENNAGATEAREA 0.247500 ;
    PORT
      LAYER met2 ;
        RECT 290.350 671.155 290.630 675.155 ;
    END
  END init
  PIN key[0]
    DIRECTION INPUT ;
    USE SIGNAL ;
    ANTENNAGATEAREA 0.159000 ;
    PORT
      LAYER met2 ;
        RECT 38.730 0.000 39.010 4.000 ;
    END
  END key[0]
  PIN key[100]
    DIRECTION INPUT ;
    USE SIGNAL ;
    ANTENNAGATEAREA 0.196500 ;
    PORT
      LAYER met2 ;
        RECT 268.730 0.000 269.010 4.000 ;
    END
  END key[100]
  PIN key[101]
    DIRECTION INPUT ;
    USE SIGNAL ;
    ANTENNAGATEAREA 0.213000 ;
    PORT
      LAYER met2 ;
        RECT 271.030 0.000 271.310 4.000 ;
    END
  END key[101]
  PIN key[102]
    DIRECTION INPUT ;
    USE SIGNAL ;
    ANTENNAGATEAREA 0.196500 ;
    PORT
      LAYER met2 ;
        RECT 273.330 0.000 273.610 4.000 ;
    END
  END key[102]
  PIN key[103]
    DIRECTION INPUT ;
    USE SIGNAL ;
    ANTENNAGATEAREA 0.213000 ;
    PORT
      LAYER met2 ;
        RECT 275.630 0.000 275.910 4.000 ;
    END
  END key[103]
  PIN key[104]
    DIRECTION INPUT ;
    USE SIGNAL ;
    ANTENNAGATEAREA 0.196500 ;
    PORT
      LAYER met2 ;
        RECT 277.930 0.000 278.210 4.000 ;
    END
  END key[104]
  PIN key[105]
    DIRECTION INPUT ;
    USE SIGNAL ;
    ANTENNAGATEAREA 0.159000 ;
    PORT
      LAYER met2 ;
        RECT 280.230 0.000 280.510 4.000 ;
    END
  END key[105]
  PIN key[106]
    DIRECTION INPUT ;
    USE SIGNAL ;
    ANTENNAGATEAREA 0.126000 ;
    PORT
      LAYER met2 ;
        RECT 282.530 0.000 282.810 4.000 ;
    END
  END key[106]
  PIN key[107]
    DIRECTION INPUT ;
    USE SIGNAL ;
    ANTENNAGATEAREA 0.126000 ;
    PORT
      LAYER met2 ;
        RECT 284.830 0.000 285.110 4.000 ;
    END
  END key[107]
  PIN key[108]
    DIRECTION INPUT ;
    USE SIGNAL ;
    ANTENNAGATEAREA 0.196500 ;
    PORT
      LAYER met2 ;
        RECT 287.130 0.000 287.410 4.000 ;
    END
  END key[108]
  PIN key[109]
    DIRECTION INPUT ;
    USE SIGNAL ;
    ANTENNAGATEAREA 0.213000 ;
    PORT
      LAYER met2 ;
        RECT 289.430 0.000 289.710 4.000 ;
    END
  END key[109]
  PIN key[10]
    DIRECTION INPUT ;
    USE SIGNAL ;
    ANTENNAGATEAREA 0.213000 ;
    PORT
      LAYER met2 ;
        RECT 61.730 0.000 62.010 4.000 ;
    END
  END key[10]
  PIN key[110]
    DIRECTION INPUT ;
    USE SIGNAL ;
    ANTENNAGATEAREA 0.159000 ;
    PORT
      LAYER met2 ;
        RECT 291.730 0.000 292.010 4.000 ;
    END
  END key[110]
  PIN key[111]
    DIRECTION INPUT ;
    USE SIGNAL ;
    ANTENNAGATEAREA 0.213000 ;
    PORT
      LAYER met2 ;
        RECT 294.030 0.000 294.310 4.000 ;
    END
  END key[111]
  PIN key[112]
    DIRECTION INPUT ;
    USE SIGNAL ;
    ANTENNAGATEAREA 0.213000 ;
    PORT
      LAYER met2 ;
        RECT 296.330 0.000 296.610 4.000 ;
    END
  END key[112]
  PIN key[113]
    DIRECTION INPUT ;
    USE SIGNAL ;
    ANTENNAGATEAREA 0.159000 ;
    PORT
      LAYER met2 ;
        RECT 298.630 0.000 298.910 4.000 ;
    END
  END key[113]
  PIN key[114]
    DIRECTION INPUT ;
    USE SIGNAL ;
    ANTENNAGATEAREA 0.213000 ;
    PORT
      LAYER met2 ;
        RECT 300.930 0.000 301.210 4.000 ;
    END
  END key[114]
  PIN key[115]
    DIRECTION INPUT ;
    USE SIGNAL ;
    ANTENNAGATEAREA 0.196500 ;
    PORT
      LAYER met2 ;
        RECT 303.230 0.000 303.510 4.000 ;
    END
  END key[115]
  PIN key[116]
    DIRECTION INPUT ;
    USE SIGNAL ;
    ANTENNAGATEAREA 0.213000 ;
    PORT
      LAYER met2 ;
        RECT 305.530 0.000 305.810 4.000 ;
    END
  END key[116]
  PIN key[117]
    DIRECTION INPUT ;
    USE SIGNAL ;
    ANTENNAGATEAREA 0.213000 ;
    PORT
      LAYER met2 ;
        RECT 307.830 0.000 308.110 4.000 ;
    END
  END key[117]
  PIN key[118]
    DIRECTION INPUT ;
    USE SIGNAL ;
    ANTENNAGATEAREA 0.126000 ;
    PORT
      LAYER met2 ;
        RECT 310.130 0.000 310.410 4.000 ;
    END
  END key[118]
  PIN key[119]
    DIRECTION INPUT ;
    USE SIGNAL ;
    ANTENNAGATEAREA 0.196500 ;
    PORT
      LAYER met2 ;
        RECT 312.430 0.000 312.710 4.000 ;
    END
  END key[119]
  PIN key[11]
    DIRECTION INPUT ;
    USE SIGNAL ;
    ANTENNAGATEAREA 0.159000 ;
    PORT
      LAYER met2 ;
        RECT 64.030 0.000 64.310 4.000 ;
    END
  END key[11]
  PIN key[120]
    DIRECTION INPUT ;
    USE SIGNAL ;
    ANTENNAGATEAREA 0.196500 ;
    PORT
      LAYER met2 ;
        RECT 314.730 0.000 315.010 4.000 ;
    END
  END key[120]
  PIN key[121]
    DIRECTION INPUT ;
    USE SIGNAL ;
    ANTENNAGATEAREA 0.196500 ;
    PORT
      LAYER met2 ;
        RECT 317.030 0.000 317.310 4.000 ;
    END
  END key[121]
  PIN key[122]
    DIRECTION INPUT ;
    USE SIGNAL ;
    ANTENNAGATEAREA 0.196500 ;
    PORT
      LAYER met2 ;
        RECT 319.330 0.000 319.610 4.000 ;
    END
  END key[122]
  PIN key[123]
    DIRECTION INPUT ;
    USE SIGNAL ;
    ANTENNAGATEAREA 0.159000 ;
    PORT
      LAYER met2 ;
        RECT 321.630 0.000 321.910 4.000 ;
    END
  END key[123]
  PIN key[124]
    DIRECTION INPUT ;
    USE SIGNAL ;
    ANTENNAGATEAREA 0.159000 ;
    PORT
      LAYER met2 ;
        RECT 323.930 0.000 324.210 4.000 ;
    END
  END key[124]
  PIN key[125]
    DIRECTION INPUT ;
    USE SIGNAL ;
    ANTENNAGATEAREA 0.213000 ;
    PORT
      LAYER met2 ;
        RECT 326.230 0.000 326.510 4.000 ;
    END
  END key[125]
  PIN key[126]
    DIRECTION INPUT ;
    USE SIGNAL ;
    ANTENNAGATEAREA 0.213000 ;
    PORT
      LAYER met2 ;
        RECT 328.530 0.000 328.810 4.000 ;
    END
  END key[126]
  PIN key[127]
    DIRECTION INPUT ;
    USE SIGNAL ;
    ANTENNAGATEAREA 0.213000 ;
    PORT
      LAYER met2 ;
        RECT 330.830 0.000 331.110 4.000 ;
    END
  END key[127]
  PIN key[128]
    DIRECTION INPUT ;
    USE SIGNAL ;
    ANTENNAGATEAREA 0.196500 ;
    PORT
      LAYER met2 ;
        RECT 333.130 0.000 333.410 4.000 ;
    END
  END key[128]
  PIN key[129]
    DIRECTION INPUT ;
    USE SIGNAL ;
    ANTENNAGATEAREA 0.213000 ;
    PORT
      LAYER met2 ;
        RECT 335.430 0.000 335.710 4.000 ;
    END
  END key[129]
  PIN key[12]
    DIRECTION INPUT ;
    USE SIGNAL ;
    ANTENNAGATEAREA 0.213000 ;
    PORT
      LAYER met2 ;
        RECT 66.330 0.000 66.610 4.000 ;
    END
  END key[12]
  PIN key[130]
    DIRECTION INPUT ;
    USE SIGNAL ;
    ANTENNAGATEAREA 0.196500 ;
    PORT
      LAYER met2 ;
        RECT 337.730 0.000 338.010 4.000 ;
    END
  END key[130]
  PIN key[131]
    DIRECTION INPUT ;
    USE SIGNAL ;
    ANTENNAGATEAREA 0.196500 ;
    PORT
      LAYER met2 ;
        RECT 340.030 0.000 340.310 4.000 ;
    END
  END key[131]
  PIN key[132]
    DIRECTION INPUT ;
    USE SIGNAL ;
    ANTENNAGATEAREA 0.196500 ;
    PORT
      LAYER met2 ;
        RECT 342.330 0.000 342.610 4.000 ;
    END
  END key[132]
  PIN key[133]
    DIRECTION INPUT ;
    USE SIGNAL ;
    ANTENNAGATEAREA 0.196500 ;
    PORT
      LAYER met2 ;
        RECT 344.630 0.000 344.910 4.000 ;
    END
  END key[133]
  PIN key[134]
    DIRECTION INPUT ;
    USE SIGNAL ;
    ANTENNAGATEAREA 0.159000 ;
    PORT
      LAYER met2 ;
        RECT 346.930 0.000 347.210 4.000 ;
    END
  END key[134]
  PIN key[135]
    DIRECTION INPUT ;
    USE SIGNAL ;
    ANTENNAGATEAREA 0.196500 ;
    PORT
      LAYER met2 ;
        RECT 349.230 0.000 349.510 4.000 ;
    END
  END key[135]
  PIN key[136]
    DIRECTION INPUT ;
    USE SIGNAL ;
    ANTENNAGATEAREA 0.196500 ;
    PORT
      LAYER met2 ;
        RECT 351.530 0.000 351.810 4.000 ;
    END
  END key[136]
  PIN key[137]
    DIRECTION INPUT ;
    USE SIGNAL ;
    ANTENNAGATEAREA 0.196500 ;
    PORT
      LAYER met2 ;
        RECT 353.830 0.000 354.110 4.000 ;
    END
  END key[137]
  PIN key[138]
    DIRECTION INPUT ;
    USE SIGNAL ;
    ANTENNAGATEAREA 0.196500 ;
    PORT
      LAYER met2 ;
        RECT 356.130 0.000 356.410 4.000 ;
    END
  END key[138]
  PIN key[139]
    DIRECTION INPUT ;
    USE SIGNAL ;
    ANTENNAGATEAREA 0.196500 ;
    PORT
      LAYER met2 ;
        RECT 358.430 0.000 358.710 4.000 ;
    END
  END key[139]
  PIN key[13]
    DIRECTION INPUT ;
    USE SIGNAL ;
    ANTENNAGATEAREA 0.159000 ;
    PORT
      LAYER met2 ;
        RECT 68.630 0.000 68.910 4.000 ;
    END
  END key[13]
  PIN key[140]
    DIRECTION INPUT ;
    USE SIGNAL ;
    ANTENNAGATEAREA 0.196500 ;
    PORT
      LAYER met2 ;
        RECT 360.730 0.000 361.010 4.000 ;
    END
  END key[140]
  PIN key[141]
    DIRECTION INPUT ;
    USE SIGNAL ;
    ANTENNAGATEAREA 0.196500 ;
    PORT
      LAYER met2 ;
        RECT 363.030 0.000 363.310 4.000 ;
    END
  END key[141]
  PIN key[142]
    DIRECTION INPUT ;
    USE SIGNAL ;
    ANTENNAGATEAREA 0.159000 ;
    PORT
      LAYER met2 ;
        RECT 365.330 0.000 365.610 4.000 ;
    END
  END key[142]
  PIN key[143]
    DIRECTION INPUT ;
    USE SIGNAL ;
    ANTENNAGATEAREA 0.196500 ;
    PORT
      LAYER met2 ;
        RECT 367.630 0.000 367.910 4.000 ;
    END
  END key[143]
  PIN key[144]
    DIRECTION INPUT ;
    USE SIGNAL ;
    ANTENNAGATEAREA 0.213000 ;
    PORT
      LAYER met2 ;
        RECT 369.930 0.000 370.210 4.000 ;
    END
  END key[144]
  PIN key[145]
    DIRECTION INPUT ;
    USE SIGNAL ;
    ANTENNAGATEAREA 0.159000 ;
    PORT
      LAYER met2 ;
        RECT 372.230 0.000 372.510 4.000 ;
    END
  END key[145]
  PIN key[146]
    DIRECTION INPUT ;
    USE SIGNAL ;
    ANTENNAGATEAREA 0.196500 ;
    PORT
      LAYER met2 ;
        RECT 374.530 0.000 374.810 4.000 ;
    END
  END key[146]
  PIN key[147]
    DIRECTION INPUT ;
    USE SIGNAL ;
    ANTENNAGATEAREA 0.196500 ;
    PORT
      LAYER met2 ;
        RECT 376.830 0.000 377.110 4.000 ;
    END
  END key[147]
  PIN key[148]
    DIRECTION INPUT ;
    USE SIGNAL ;
    ANTENNAGATEAREA 0.213000 ;
    PORT
      LAYER met2 ;
        RECT 379.130 0.000 379.410 4.000 ;
    END
  END key[148]
  PIN key[149]
    DIRECTION INPUT ;
    USE SIGNAL ;
    ANTENNAGATEAREA 0.213000 ;
    PORT
      LAYER met2 ;
        RECT 381.430 0.000 381.710 4.000 ;
    END
  END key[149]
  PIN key[14]
    DIRECTION INPUT ;
    USE SIGNAL ;
    ANTENNAGATEAREA 0.213000 ;
    PORT
      LAYER met2 ;
        RECT 70.930 0.000 71.210 4.000 ;
    END
  END key[14]
  PIN key[150]
    DIRECTION INPUT ;
    USE SIGNAL ;
    ANTENNAGATEAREA 0.213000 ;
    PORT
      LAYER met2 ;
        RECT 383.730 0.000 384.010 4.000 ;
    END
  END key[150]
  PIN key[151]
    DIRECTION INPUT ;
    USE SIGNAL ;
    ANTENNAGATEAREA 0.196500 ;
    PORT
      LAYER met2 ;
        RECT 386.030 0.000 386.310 4.000 ;
    END
  END key[151]
  PIN key[152]
    DIRECTION INPUT ;
    USE SIGNAL ;
    ANTENNAGATEAREA 0.213000 ;
    PORT
      LAYER met2 ;
        RECT 388.330 0.000 388.610 4.000 ;
    END
  END key[152]
  PIN key[153]
    DIRECTION INPUT ;
    USE SIGNAL ;
    ANTENNAGATEAREA 0.213000 ;
    PORT
      LAYER met2 ;
        RECT 390.630 0.000 390.910 4.000 ;
    END
  END key[153]
  PIN key[154]
    DIRECTION INPUT ;
    USE SIGNAL ;
    ANTENNAGATEAREA 0.196500 ;
    PORT
      LAYER met2 ;
        RECT 392.930 0.000 393.210 4.000 ;
    END
  END key[154]
  PIN key[155]
    DIRECTION INPUT ;
    USE SIGNAL ;
    ANTENNAGATEAREA 0.213000 ;
    PORT
      LAYER met2 ;
        RECT 395.230 0.000 395.510 4.000 ;
    END
  END key[155]
  PIN key[156]
    DIRECTION INPUT ;
    USE SIGNAL ;
    ANTENNAGATEAREA 0.159000 ;
    PORT
      LAYER met2 ;
        RECT 397.530 0.000 397.810 4.000 ;
    END
  END key[156]
  PIN key[157]
    DIRECTION INPUT ;
    USE SIGNAL ;
    ANTENNAGATEAREA 0.213000 ;
    PORT
      LAYER met2 ;
        RECT 399.830 0.000 400.110 4.000 ;
    END
  END key[157]
  PIN key[158]
    DIRECTION INPUT ;
    USE SIGNAL ;
    ANTENNAGATEAREA 0.126000 ;
    PORT
      LAYER met2 ;
        RECT 402.130 0.000 402.410 4.000 ;
    END
  END key[158]
  PIN key[159]
    DIRECTION INPUT ;
    USE SIGNAL ;
    ANTENNAGATEAREA 0.213000 ;
    PORT
      LAYER met2 ;
        RECT 404.430 0.000 404.710 4.000 ;
    END
  END key[159]
  PIN key[15]
    DIRECTION INPUT ;
    USE SIGNAL ;
    ANTENNAGATEAREA 0.213000 ;
    PORT
      LAYER met2 ;
        RECT 73.230 0.000 73.510 4.000 ;
    END
  END key[15]
  PIN key[160]
    DIRECTION INPUT ;
    USE SIGNAL ;
    ANTENNAGATEAREA 0.196500 ;
    PORT
      LAYER met2 ;
        RECT 406.730 0.000 407.010 4.000 ;
    END
  END key[160]
  PIN key[161]
    DIRECTION INPUT ;
    USE SIGNAL ;
    ANTENNAGATEAREA 0.126000 ;
    PORT
      LAYER met2 ;
        RECT 409.030 0.000 409.310 4.000 ;
    END
  END key[161]
  PIN key[162]
    DIRECTION INPUT ;
    USE SIGNAL ;
    ANTENNAGATEAREA 0.196500 ;
    PORT
      LAYER met2 ;
        RECT 411.330 0.000 411.610 4.000 ;
    END
  END key[162]
  PIN key[163]
    DIRECTION INPUT ;
    USE SIGNAL ;
    ANTENNAGATEAREA 0.196500 ;
    PORT
      LAYER met2 ;
        RECT 413.630 0.000 413.910 4.000 ;
    END
  END key[163]
  PIN key[164]
    DIRECTION INPUT ;
    USE SIGNAL ;
    ANTENNAGATEAREA 0.196500 ;
    PORT
      LAYER met2 ;
        RECT 415.930 0.000 416.210 4.000 ;
    END
  END key[164]
  PIN key[165]
    DIRECTION INPUT ;
    USE SIGNAL ;
    ANTENNAGATEAREA 0.196500 ;
    PORT
      LAYER met2 ;
        RECT 418.230 0.000 418.510 4.000 ;
    END
  END key[165]
  PIN key[166]
    DIRECTION INPUT ;
    USE SIGNAL ;
    ANTENNAGATEAREA 0.196500 ;
    PORT
      LAYER met2 ;
        RECT 420.530 0.000 420.810 4.000 ;
    END
  END key[166]
  PIN key[167]
    DIRECTION INPUT ;
    USE SIGNAL ;
    ANTENNAGATEAREA 0.196500 ;
    PORT
      LAYER met2 ;
        RECT 422.830 0.000 423.110 4.000 ;
    END
  END key[167]
  PIN key[168]
    DIRECTION INPUT ;
    USE SIGNAL ;
    ANTENNAGATEAREA 0.196500 ;
    PORT
      LAYER met2 ;
        RECT 425.130 0.000 425.410 4.000 ;
    END
  END key[168]
  PIN key[169]
    DIRECTION INPUT ;
    USE SIGNAL ;
    ANTENNAGATEAREA 0.196500 ;
    PORT
      LAYER met2 ;
        RECT 427.430 0.000 427.710 4.000 ;
    END
  END key[169]
  PIN key[16]
    DIRECTION INPUT ;
    USE SIGNAL ;
    ANTENNAGATEAREA 0.213000 ;
    PORT
      LAYER met2 ;
        RECT 75.530 0.000 75.810 4.000 ;
    END
  END key[16]
  PIN key[170]
    DIRECTION INPUT ;
    USE SIGNAL ;
    ANTENNAGATEAREA 0.196500 ;
    PORT
      LAYER met2 ;
        RECT 429.730 0.000 430.010 4.000 ;
    END
  END key[170]
  PIN key[171]
    DIRECTION INPUT ;
    USE SIGNAL ;
    ANTENNAGATEAREA 0.196500 ;
    PORT
      LAYER met2 ;
        RECT 432.030 0.000 432.310 4.000 ;
    END
  END key[171]
  PIN key[172]
    DIRECTION INPUT ;
    USE SIGNAL ;
    ANTENNAGATEAREA 0.196500 ;
    PORT
      LAYER met2 ;
        RECT 434.330 0.000 434.610 4.000 ;
    END
  END key[172]
  PIN key[173]
    DIRECTION INPUT ;
    USE SIGNAL ;
    ANTENNAGATEAREA 0.196500 ;
    PORT
      LAYER met2 ;
        RECT 436.630 0.000 436.910 4.000 ;
    END
  END key[173]
  PIN key[174]
    DIRECTION INPUT ;
    USE SIGNAL ;
    ANTENNAGATEAREA 0.196500 ;
    PORT
      LAYER met2 ;
        RECT 438.930 0.000 439.210 4.000 ;
    END
  END key[174]
  PIN key[175]
    DIRECTION INPUT ;
    USE SIGNAL ;
    ANTENNAGATEAREA 0.196500 ;
    PORT
      LAYER met2 ;
        RECT 441.230 0.000 441.510 4.000 ;
    END
  END key[175]
  PIN key[176]
    DIRECTION INPUT ;
    USE SIGNAL ;
    ANTENNAGATEAREA 0.196500 ;
    PORT
      LAYER met2 ;
        RECT 443.530 0.000 443.810 4.000 ;
    END
  END key[176]
  PIN key[177]
    DIRECTION INPUT ;
    USE SIGNAL ;
    ANTENNAGATEAREA 0.213000 ;
    PORT
      LAYER met2 ;
        RECT 445.830 0.000 446.110 4.000 ;
    END
  END key[177]
  PIN key[178]
    DIRECTION INPUT ;
    USE SIGNAL ;
    ANTENNAGATEAREA 0.196500 ;
    PORT
      LAYER met2 ;
        RECT 448.130 0.000 448.410 4.000 ;
    END
  END key[178]
  PIN key[179]
    DIRECTION INPUT ;
    USE SIGNAL ;
    ANTENNAGATEAREA 0.126000 ;
    PORT
      LAYER met2 ;
        RECT 450.430 0.000 450.710 4.000 ;
    END
  END key[179]
  PIN key[17]
    DIRECTION INPUT ;
    USE SIGNAL ;
    ANTENNAGATEAREA 0.196500 ;
    PORT
      LAYER met2 ;
        RECT 77.830 0.000 78.110 4.000 ;
    END
  END key[17]
  PIN key[180]
    DIRECTION INPUT ;
    USE SIGNAL ;
    ANTENNAGATEAREA 0.196500 ;
    PORT
      LAYER met2 ;
        RECT 452.730 0.000 453.010 4.000 ;
    END
  END key[180]
  PIN key[181]
    DIRECTION INPUT ;
    USE SIGNAL ;
    ANTENNAGATEAREA 0.196500 ;
    PORT
      LAYER met2 ;
        RECT 455.030 0.000 455.310 4.000 ;
    END
  END key[181]
  PIN key[182]
    DIRECTION INPUT ;
    USE SIGNAL ;
    ANTENNAGATEAREA 0.196500 ;
    PORT
      LAYER met2 ;
        RECT 457.330 0.000 457.610 4.000 ;
    END
  END key[182]
  PIN key[183]
    DIRECTION INPUT ;
    USE SIGNAL ;
    ANTENNAGATEAREA 0.196500 ;
    PORT
      LAYER met2 ;
        RECT 459.630 0.000 459.910 4.000 ;
    END
  END key[183]
  PIN key[184]
    DIRECTION INPUT ;
    USE SIGNAL ;
    ANTENNAGATEAREA 0.196500 ;
    PORT
      LAYER met2 ;
        RECT 461.930 0.000 462.210 4.000 ;
    END
  END key[184]
  PIN key[185]
    DIRECTION INPUT ;
    USE SIGNAL ;
    ANTENNAGATEAREA 0.196500 ;
    PORT
      LAYER met2 ;
        RECT 464.230 0.000 464.510 4.000 ;
    END
  END key[185]
  PIN key[186]
    DIRECTION INPUT ;
    USE SIGNAL ;
    ANTENNAGATEAREA 0.196500 ;
    PORT
      LAYER met2 ;
        RECT 466.530 0.000 466.810 4.000 ;
    END
  END key[186]
  PIN key[187]
    DIRECTION INPUT ;
    USE SIGNAL ;
    ANTENNAGATEAREA 0.196500 ;
    PORT
      LAYER met2 ;
        RECT 468.830 0.000 469.110 4.000 ;
    END
  END key[187]
  PIN key[188]
    DIRECTION INPUT ;
    USE SIGNAL ;
    ANTENNAGATEAREA 0.196500 ;
    PORT
      LAYER met2 ;
        RECT 471.130 0.000 471.410 4.000 ;
    END
  END key[188]
  PIN key[189]
    DIRECTION INPUT ;
    USE SIGNAL ;
    ANTENNAGATEAREA 0.196500 ;
    PORT
      LAYER met2 ;
        RECT 473.430 0.000 473.710 4.000 ;
    END
  END key[189]
  PIN key[18]
    DIRECTION INPUT ;
    USE SIGNAL ;
    ANTENNAGATEAREA 0.213000 ;
    PORT
      LAYER met2 ;
        RECT 80.130 0.000 80.410 4.000 ;
    END
  END key[18]
  PIN key[190]
    DIRECTION INPUT ;
    USE SIGNAL ;
    ANTENNAGATEAREA 0.196500 ;
    PORT
      LAYER met2 ;
        RECT 475.730 0.000 476.010 4.000 ;
    END
  END key[190]
  PIN key[191]
    DIRECTION INPUT ;
    USE SIGNAL ;
    ANTENNAGATEAREA 0.196500 ;
    PORT
      LAYER met2 ;
        RECT 478.030 0.000 478.310 4.000 ;
    END
  END key[191]
  PIN key[192]
    DIRECTION INPUT ;
    USE SIGNAL ;
    ANTENNAGATEAREA 0.196500 ;
    PORT
      LAYER met2 ;
        RECT 480.330 0.000 480.610 4.000 ;
    END
  END key[192]
  PIN key[193]
    DIRECTION INPUT ;
    USE SIGNAL ;
    ANTENNAGATEAREA 0.213000 ;
    PORT
      LAYER met2 ;
        RECT 482.630 0.000 482.910 4.000 ;
    END
  END key[193]
  PIN key[194]
    DIRECTION INPUT ;
    USE SIGNAL ;
    ANTENNAGATEAREA 0.196500 ;
    PORT
      LAYER met2 ;
        RECT 484.930 0.000 485.210 4.000 ;
    END
  END key[194]
  PIN key[195]
    DIRECTION INPUT ;
    USE SIGNAL ;
    ANTENNAGATEAREA 0.196500 ;
    PORT
      LAYER met2 ;
        RECT 487.230 0.000 487.510 4.000 ;
    END
  END key[195]
  PIN key[196]
    DIRECTION INPUT ;
    USE SIGNAL ;
    ANTENNAGATEAREA 0.196500 ;
    PORT
      LAYER met2 ;
        RECT 489.530 0.000 489.810 4.000 ;
    END
  END key[196]
  PIN key[197]
    DIRECTION INPUT ;
    USE SIGNAL ;
    ANTENNAGATEAREA 0.196500 ;
    PORT
      LAYER met2 ;
        RECT 491.830 0.000 492.110 4.000 ;
    END
  END key[197]
  PIN key[198]
    DIRECTION INPUT ;
    USE SIGNAL ;
    ANTENNAGATEAREA 0.196500 ;
    PORT
      LAYER met2 ;
        RECT 494.130 0.000 494.410 4.000 ;
    END
  END key[198]
  PIN key[199]
    DIRECTION INPUT ;
    USE SIGNAL ;
    ANTENNAGATEAREA 0.196500 ;
    PORT
      LAYER met2 ;
        RECT 496.430 0.000 496.710 4.000 ;
    END
  END key[199]
  PIN key[19]
    DIRECTION INPUT ;
    USE SIGNAL ;
    ANTENNAGATEAREA 0.159000 ;
    PORT
      LAYER met2 ;
        RECT 82.430 0.000 82.710 4.000 ;
    END
  END key[19]
  PIN key[1]
    DIRECTION INPUT ;
    USE SIGNAL ;
    ANTENNAGATEAREA 0.213000 ;
    PORT
      LAYER met2 ;
        RECT 41.030 0.000 41.310 4.000 ;
    END
  END key[1]
  PIN key[200]
    DIRECTION INPUT ;
    USE SIGNAL ;
    ANTENNAGATEAREA 0.196500 ;
    PORT
      LAYER met2 ;
        RECT 498.730 0.000 499.010 4.000 ;
    END
  END key[200]
  PIN key[201]
    DIRECTION INPUT ;
    USE SIGNAL ;
    ANTENNAGATEAREA 0.196500 ;
    PORT
      LAYER met2 ;
        RECT 501.030 0.000 501.310 4.000 ;
    END
  END key[201]
  PIN key[202]
    DIRECTION INPUT ;
    USE SIGNAL ;
    ANTENNAGATEAREA 0.196500 ;
    PORT
      LAYER met2 ;
        RECT 503.330 0.000 503.610 4.000 ;
    END
  END key[202]
  PIN key[203]
    DIRECTION INPUT ;
    USE SIGNAL ;
    ANTENNAGATEAREA 0.196500 ;
    PORT
      LAYER met2 ;
        RECT 505.630 0.000 505.910 4.000 ;
    END
  END key[203]
  PIN key[204]
    DIRECTION INPUT ;
    USE SIGNAL ;
    ANTENNAGATEAREA 0.126000 ;
    PORT
      LAYER met2 ;
        RECT 507.930 0.000 508.210 4.000 ;
    END
  END key[204]
  PIN key[205]
    DIRECTION INPUT ;
    USE SIGNAL ;
    ANTENNAGATEAREA 0.196500 ;
    PORT
      LAYER met2 ;
        RECT 510.230 0.000 510.510 4.000 ;
    END
  END key[205]
  PIN key[206]
    DIRECTION INPUT ;
    USE SIGNAL ;
    ANTENNAGATEAREA 0.196500 ;
    PORT
      LAYER met2 ;
        RECT 512.530 0.000 512.810 4.000 ;
    END
  END key[206]
  PIN key[207]
    DIRECTION INPUT ;
    USE SIGNAL ;
    ANTENNAGATEAREA 0.196500 ;
    PORT
      LAYER met2 ;
        RECT 514.830 0.000 515.110 4.000 ;
    END
  END key[207]
  PIN key[208]
    DIRECTION INPUT ;
    USE SIGNAL ;
    ANTENNAGATEAREA 0.196500 ;
    PORT
      LAYER met2 ;
        RECT 517.130 0.000 517.410 4.000 ;
    END
  END key[208]
  PIN key[209]
    DIRECTION INPUT ;
    USE SIGNAL ;
    ANTENNAGATEAREA 0.196500 ;
    PORT
      LAYER met2 ;
        RECT 519.430 0.000 519.710 4.000 ;
    END
  END key[209]
  PIN key[20]
    DIRECTION INPUT ;
    USE SIGNAL ;
    ANTENNAGATEAREA 0.213000 ;
    PORT
      LAYER met2 ;
        RECT 84.730 0.000 85.010 4.000 ;
    END
  END key[20]
  PIN key[210]
    DIRECTION INPUT ;
    USE SIGNAL ;
    ANTENNAGATEAREA 0.196500 ;
    PORT
      LAYER met2 ;
        RECT 521.730 0.000 522.010 4.000 ;
    END
  END key[210]
  PIN key[211]
    DIRECTION INPUT ;
    USE SIGNAL ;
    ANTENNAGATEAREA 0.213000 ;
    PORT
      LAYER met2 ;
        RECT 524.030 0.000 524.310 4.000 ;
    END
  END key[211]
  PIN key[212]
    DIRECTION INPUT ;
    USE SIGNAL ;
    ANTENNAGATEAREA 0.196500 ;
    PORT
      LAYER met2 ;
        RECT 526.330 0.000 526.610 4.000 ;
    END
  END key[212]
  PIN key[213]
    DIRECTION INPUT ;
    USE SIGNAL ;
    ANTENNAGATEAREA 0.196500 ;
    PORT
      LAYER met2 ;
        RECT 528.630 0.000 528.910 4.000 ;
    END
  END key[213]
  PIN key[214]
    DIRECTION INPUT ;
    USE SIGNAL ;
    ANTENNAGATEAREA 0.196500 ;
    PORT
      LAYER met2 ;
        RECT 530.930 0.000 531.210 4.000 ;
    END
  END key[214]
  PIN key[215]
    DIRECTION INPUT ;
    USE SIGNAL ;
    ANTENNAGATEAREA 0.196500 ;
    PORT
      LAYER met2 ;
        RECT 533.230 0.000 533.510 4.000 ;
    END
  END key[215]
  PIN key[216]
    DIRECTION INPUT ;
    USE SIGNAL ;
    ANTENNAGATEAREA 0.213000 ;
    PORT
      LAYER met2 ;
        RECT 535.530 0.000 535.810 4.000 ;
    END
  END key[216]
  PIN key[217]
    DIRECTION INPUT ;
    USE SIGNAL ;
    ANTENNAGATEAREA 0.196500 ;
    PORT
      LAYER met2 ;
        RECT 537.830 0.000 538.110 4.000 ;
    END
  END key[217]
  PIN key[218]
    DIRECTION INPUT ;
    USE SIGNAL ;
    ANTENNAGATEAREA 0.196500 ;
    PORT
      LAYER met2 ;
        RECT 540.130 0.000 540.410 4.000 ;
    END
  END key[218]
  PIN key[219]
    DIRECTION INPUT ;
    USE SIGNAL ;
    ANTENNAGATEAREA 0.196500 ;
    PORT
      LAYER met2 ;
        RECT 542.430 0.000 542.710 4.000 ;
    END
  END key[219]
  PIN key[21]
    DIRECTION INPUT ;
    USE SIGNAL ;
    ANTENNAGATEAREA 0.213000 ;
    PORT
      LAYER met2 ;
        RECT 87.030 0.000 87.310 4.000 ;
    END
  END key[21]
  PIN key[220]
    DIRECTION INPUT ;
    USE SIGNAL ;
    ANTENNAGATEAREA 0.196500 ;
    PORT
      LAYER met2 ;
        RECT 544.730 0.000 545.010 4.000 ;
    END
  END key[220]
  PIN key[221]
    DIRECTION INPUT ;
    USE SIGNAL ;
    ANTENNAGATEAREA 0.196500 ;
    PORT
      LAYER met2 ;
        RECT 547.030 0.000 547.310 4.000 ;
    END
  END key[221]
  PIN key[222]
    DIRECTION INPUT ;
    USE SIGNAL ;
    ANTENNAGATEAREA 0.196500 ;
    PORT
      LAYER met2 ;
        RECT 549.330 0.000 549.610 4.000 ;
    END
  END key[222]
  PIN key[223]
    DIRECTION INPUT ;
    USE SIGNAL ;
    ANTENNAGATEAREA 0.196500 ;
    PORT
      LAYER met2 ;
        RECT 551.630 0.000 551.910 4.000 ;
    END
  END key[223]
  PIN key[224]
    DIRECTION INPUT ;
    USE SIGNAL ;
    ANTENNAGATEAREA 0.196500 ;
    PORT
      LAYER met2 ;
        RECT 553.930 0.000 554.210 4.000 ;
    END
  END key[224]
  PIN key[225]
    DIRECTION INPUT ;
    USE SIGNAL ;
    ANTENNAGATEAREA 0.213000 ;
    PORT
      LAYER met2 ;
        RECT 556.230 0.000 556.510 4.000 ;
    END
  END key[225]
  PIN key[226]
    DIRECTION INPUT ;
    USE SIGNAL ;
    ANTENNAGATEAREA 0.196500 ;
    PORT
      LAYER met2 ;
        RECT 558.530 0.000 558.810 4.000 ;
    END
  END key[226]
  PIN key[227]
    DIRECTION INPUT ;
    USE SIGNAL ;
    ANTENNAGATEAREA 0.213000 ;
    PORT
      LAYER met2 ;
        RECT 560.830 0.000 561.110 4.000 ;
    END
  END key[227]
  PIN key[228]
    DIRECTION INPUT ;
    USE SIGNAL ;
    ANTENNAGATEAREA 0.159000 ;
    PORT
      LAYER met2 ;
        RECT 563.130 0.000 563.410 4.000 ;
    END
  END key[228]
  PIN key[229]
    DIRECTION INPUT ;
    USE SIGNAL ;
    ANTENNAGATEAREA 0.196500 ;
    PORT
      LAYER met2 ;
        RECT 565.430 0.000 565.710 4.000 ;
    END
  END key[229]
  PIN key[22]
    DIRECTION INPUT ;
    USE SIGNAL ;
    ANTENNAGATEAREA 0.159000 ;
    PORT
      LAYER met2 ;
        RECT 89.330 0.000 89.610 4.000 ;
    END
  END key[22]
  PIN key[230]
    DIRECTION INPUT ;
    USE SIGNAL ;
    ANTENNAGATEAREA 0.213000 ;
    PORT
      LAYER met2 ;
        RECT 567.730 0.000 568.010 4.000 ;
    END
  END key[230]
  PIN key[231]
    DIRECTION INPUT ;
    USE SIGNAL ;
    ANTENNAGATEAREA 0.196500 ;
    PORT
      LAYER met2 ;
        RECT 570.030 0.000 570.310 4.000 ;
    END
  END key[231]
  PIN key[232]
    DIRECTION INPUT ;
    USE SIGNAL ;
    ANTENNAGATEAREA 0.159000 ;
    PORT
      LAYER met2 ;
        RECT 572.330 0.000 572.610 4.000 ;
    END
  END key[232]
  PIN key[233]
    DIRECTION INPUT ;
    USE SIGNAL ;
    ANTENNAGATEAREA 0.196500 ;
    PORT
      LAYER met2 ;
        RECT 574.630 0.000 574.910 4.000 ;
    END
  END key[233]
  PIN key[234]
    DIRECTION INPUT ;
    USE SIGNAL ;
    ANTENNAGATEAREA 0.196500 ;
    PORT
      LAYER met2 ;
        RECT 576.930 0.000 577.210 4.000 ;
    END
  END key[234]
  PIN key[235]
    DIRECTION INPUT ;
    USE SIGNAL ;
    ANTENNAGATEAREA 0.196500 ;
    PORT
      LAYER met2 ;
        RECT 579.230 0.000 579.510 4.000 ;
    END
  END key[235]
  PIN key[236]
    DIRECTION INPUT ;
    USE SIGNAL ;
    ANTENNAGATEAREA 0.213000 ;
    PORT
      LAYER met2 ;
        RECT 581.530 0.000 581.810 4.000 ;
    END
  END key[236]
  PIN key[237]
    DIRECTION INPUT ;
    USE SIGNAL ;
    ANTENNAGATEAREA 0.213000 ;
    PORT
      LAYER met2 ;
        RECT 583.830 0.000 584.110 4.000 ;
    END
  END key[237]
  PIN key[238]
    DIRECTION INPUT ;
    USE SIGNAL ;
    ANTENNAGATEAREA 0.196500 ;
    PORT
      LAYER met2 ;
        RECT 586.130 0.000 586.410 4.000 ;
    END
  END key[238]
  PIN key[239]
    DIRECTION INPUT ;
    USE SIGNAL ;
    ANTENNAGATEAREA 0.196500 ;
    PORT
      LAYER met2 ;
        RECT 588.430 0.000 588.710 4.000 ;
    END
  END key[239]
  PIN key[23]
    DIRECTION INPUT ;
    USE SIGNAL ;
    ANTENNAGATEAREA 0.159000 ;
    PORT
      LAYER met2 ;
        RECT 91.630 0.000 91.910 4.000 ;
    END
  END key[23]
  PIN key[240]
    DIRECTION INPUT ;
    USE SIGNAL ;
    ANTENNAGATEAREA 0.196500 ;
    PORT
      LAYER met2 ;
        RECT 590.730 0.000 591.010 4.000 ;
    END
  END key[240]
  PIN key[241]
    DIRECTION INPUT ;
    USE SIGNAL ;
    ANTENNAGATEAREA 0.196500 ;
    PORT
      LAYER met2 ;
        RECT 593.030 0.000 593.310 4.000 ;
    END
  END key[241]
  PIN key[242]
    DIRECTION INPUT ;
    USE SIGNAL ;
    ANTENNAGATEAREA 0.196500 ;
    PORT
      LAYER met2 ;
        RECT 595.330 0.000 595.610 4.000 ;
    END
  END key[242]
  PIN key[243]
    DIRECTION INPUT ;
    USE SIGNAL ;
    ANTENNAGATEAREA 0.196500 ;
    PORT
      LAYER met2 ;
        RECT 597.630 0.000 597.910 4.000 ;
    END
  END key[243]
  PIN key[244]
    DIRECTION INPUT ;
    USE SIGNAL ;
    ANTENNAGATEAREA 0.196500 ;
    PORT
      LAYER met2 ;
        RECT 599.930 0.000 600.210 4.000 ;
    END
  END key[244]
  PIN key[245]
    DIRECTION INPUT ;
    USE SIGNAL ;
    ANTENNAGATEAREA 0.213000 ;
    PORT
      LAYER met2 ;
        RECT 602.230 0.000 602.510 4.000 ;
    END
  END key[245]
  PIN key[246]
    DIRECTION INPUT ;
    USE SIGNAL ;
    ANTENNAGATEAREA 0.196500 ;
    PORT
      LAYER met2 ;
        RECT 604.530 0.000 604.810 4.000 ;
    END
  END key[246]
  PIN key[247]
    DIRECTION INPUT ;
    USE SIGNAL ;
    ANTENNAGATEAREA 0.196500 ;
    PORT
      LAYER met2 ;
        RECT 606.830 0.000 607.110 4.000 ;
    END
  END key[247]
  PIN key[248]
    DIRECTION INPUT ;
    USE SIGNAL ;
    ANTENNAGATEAREA 0.159000 ;
    PORT
      LAYER met2 ;
        RECT 609.130 0.000 609.410 4.000 ;
    END
  END key[248]
  PIN key[249]
    DIRECTION INPUT ;
    USE SIGNAL ;
    ANTENNAGATEAREA 0.196500 ;
    PORT
      LAYER met2 ;
        RECT 611.430 0.000 611.710 4.000 ;
    END
  END key[249]
  PIN key[24]
    DIRECTION INPUT ;
    USE SIGNAL ;
    ANTENNAGATEAREA 0.159000 ;
    PORT
      LAYER met2 ;
        RECT 93.930 0.000 94.210 4.000 ;
    END
  END key[24]
  PIN key[250]
    DIRECTION INPUT ;
    USE SIGNAL ;
    ANTENNAGATEAREA 0.159000 ;
    PORT
      LAYER met2 ;
        RECT 613.730 0.000 614.010 4.000 ;
    END
  END key[250]
  PIN key[251]
    DIRECTION INPUT ;
    USE SIGNAL ;
    ANTENNAGATEAREA 0.126000 ;
    PORT
      LAYER met2 ;
        RECT 616.030 0.000 616.310 4.000 ;
    END
  END key[251]
  PIN key[252]
    DIRECTION INPUT ;
    USE SIGNAL ;
    ANTENNAGATEAREA 0.213000 ;
    PORT
      LAYER met2 ;
        RECT 618.330 0.000 618.610 4.000 ;
    END
  END key[252]
  PIN key[253]
    DIRECTION INPUT ;
    USE SIGNAL ;
    ANTENNAGATEAREA 0.196500 ;
    PORT
      LAYER met2 ;
        RECT 620.630 0.000 620.910 4.000 ;
    END
  END key[253]
  PIN key[254]
    DIRECTION INPUT ;
    USE SIGNAL ;
    ANTENNAGATEAREA 0.196500 ;
    PORT
      LAYER met2 ;
        RECT 622.930 0.000 623.210 4.000 ;
    END
  END key[254]
  PIN key[255]
    DIRECTION INPUT ;
    USE SIGNAL ;
    ANTENNAGATEAREA 0.196500 ;
    PORT
      LAYER met2 ;
        RECT 625.230 0.000 625.510 4.000 ;
    END
  END key[255]
  PIN key[25]
    DIRECTION INPUT ;
    USE SIGNAL ;
    ANTENNAGATEAREA 0.213000 ;
    PORT
      LAYER met2 ;
        RECT 96.230 0.000 96.510 4.000 ;
    END
  END key[25]
  PIN key[26]
    DIRECTION INPUT ;
    USE SIGNAL ;
    ANTENNAGATEAREA 0.159000 ;
    PORT
      LAYER met2 ;
        RECT 98.530 0.000 98.810 4.000 ;
    END
  END key[26]
  PIN key[27]
    DIRECTION INPUT ;
    USE SIGNAL ;
    ANTENNAGATEAREA 0.196500 ;
    PORT
      LAYER met2 ;
        RECT 100.830 0.000 101.110 4.000 ;
    END
  END key[27]
  PIN key[28]
    DIRECTION INPUT ;
    USE SIGNAL ;
    ANTENNAGATEAREA 0.247500 ;
    PORT
      LAYER met2 ;
        RECT 103.130 0.000 103.410 4.000 ;
    END
  END key[28]
  PIN key[29]
    DIRECTION INPUT ;
    USE SIGNAL ;
    ANTENNAGATEAREA 0.196500 ;
    PORT
      LAYER met2 ;
        RECT 105.430 0.000 105.710 4.000 ;
    END
  END key[29]
  PIN key[2]
    DIRECTION INPUT ;
    USE SIGNAL ;
    ANTENNAGATEAREA 0.159000 ;
    PORT
      LAYER met2 ;
        RECT 43.330 0.000 43.610 4.000 ;
    END
  END key[2]
  PIN key[30]
    DIRECTION INPUT ;
    USE SIGNAL ;
    ANTENNAGATEAREA 0.213000 ;
    PORT
      LAYER met2 ;
        RECT 107.730 0.000 108.010 4.000 ;
    END
  END key[30]
  PIN key[31]
    DIRECTION INPUT ;
    USE SIGNAL ;
    ANTENNAGATEAREA 0.213000 ;
    PORT
      LAYER met2 ;
        RECT 110.030 0.000 110.310 4.000 ;
    END
  END key[31]
  PIN key[32]
    DIRECTION INPUT ;
    USE SIGNAL ;
    ANTENNAGATEAREA 0.126000 ;
    PORT
      LAYER met2 ;
        RECT 112.330 0.000 112.610 4.000 ;
    END
  END key[32]
  PIN key[33]
    DIRECTION INPUT ;
    USE SIGNAL ;
    ANTENNAGATEAREA 0.213000 ;
    PORT
      LAYER met2 ;
        RECT 114.630 0.000 114.910 4.000 ;
    END
  END key[33]
  PIN key[34]
    DIRECTION INPUT ;
    USE SIGNAL ;
    ANTENNAGATEAREA 0.159000 ;
    PORT
      LAYER met2 ;
        RECT 116.930 0.000 117.210 4.000 ;
    END
  END key[34]
  PIN key[35]
    DIRECTION INPUT ;
    USE SIGNAL ;
    ANTENNAGATEAREA 0.213000 ;
    PORT
      LAYER met2 ;
        RECT 119.230 0.000 119.510 4.000 ;
    END
  END key[35]
  PIN key[36]
    DIRECTION INPUT ;
    USE SIGNAL ;
    ANTENNAGATEAREA 0.126000 ;
    PORT
      LAYER met2 ;
        RECT 121.530 0.000 121.810 4.000 ;
    END
  END key[36]
  PIN key[37]
    DIRECTION INPUT ;
    USE SIGNAL ;
    ANTENNAGATEAREA 0.159000 ;
    PORT
      LAYER met2 ;
        RECT 123.830 0.000 124.110 4.000 ;
    END
  END key[37]
  PIN key[38]
    DIRECTION INPUT ;
    USE SIGNAL ;
    ANTENNAGATEAREA 0.196500 ;
    PORT
      LAYER met2 ;
        RECT 126.130 0.000 126.410 4.000 ;
    END
  END key[38]
  PIN key[39]
    DIRECTION INPUT ;
    USE SIGNAL ;
    ANTENNAGATEAREA 0.213000 ;
    PORT
      LAYER met2 ;
        RECT 128.430 0.000 128.710 4.000 ;
    END
  END key[39]
  PIN key[3]
    DIRECTION INPUT ;
    USE SIGNAL ;
    ANTENNAGATEAREA 0.213000 ;
    PORT
      LAYER met2 ;
        RECT 45.630 0.000 45.910 4.000 ;
    END
  END key[3]
  PIN key[40]
    DIRECTION INPUT ;
    USE SIGNAL ;
    ANTENNAGATEAREA 0.213000 ;
    PORT
      LAYER met2 ;
        RECT 130.730 0.000 131.010 4.000 ;
    END
  END key[40]
  PIN key[41]
    DIRECTION INPUT ;
    USE SIGNAL ;
    ANTENNAGATEAREA 0.196500 ;
    PORT
      LAYER met2 ;
        RECT 133.030 0.000 133.310 4.000 ;
    END
  END key[41]
  PIN key[42]
    DIRECTION INPUT ;
    USE SIGNAL ;
    ANTENNAGATEAREA 0.213000 ;
    PORT
      LAYER met2 ;
        RECT 135.330 0.000 135.610 4.000 ;
    END
  END key[42]
  PIN key[43]
    DIRECTION INPUT ;
    USE SIGNAL ;
    ANTENNAGATEAREA 0.196500 ;
    PORT
      LAYER met2 ;
        RECT 137.630 0.000 137.910 4.000 ;
    END
  END key[43]
  PIN key[44]
    DIRECTION INPUT ;
    USE SIGNAL ;
    ANTENNAGATEAREA 0.196500 ;
    PORT
      LAYER met2 ;
        RECT 139.930 0.000 140.210 4.000 ;
    END
  END key[44]
  PIN key[45]
    DIRECTION INPUT ;
    USE SIGNAL ;
    ANTENNAGATEAREA 0.213000 ;
    PORT
      LAYER met2 ;
        RECT 142.230 0.000 142.510 4.000 ;
    END
  END key[45]
  PIN key[46]
    DIRECTION INPUT ;
    USE SIGNAL ;
    ANTENNAGATEAREA 0.213000 ;
    PORT
      LAYER met2 ;
        RECT 144.530 0.000 144.810 4.000 ;
    END
  END key[46]
  PIN key[47]
    DIRECTION INPUT ;
    USE SIGNAL ;
    ANTENNAGATEAREA 0.196500 ;
    PORT
      LAYER met2 ;
        RECT 146.830 0.000 147.110 4.000 ;
    END
  END key[47]
  PIN key[48]
    DIRECTION INPUT ;
    USE SIGNAL ;
    ANTENNAGATEAREA 0.213000 ;
    PORT
      LAYER met2 ;
        RECT 149.130 0.000 149.410 4.000 ;
    END
  END key[48]
  PIN key[49]
    DIRECTION INPUT ;
    USE SIGNAL ;
    ANTENNAGATEAREA 0.213000 ;
    PORT
      LAYER met2 ;
        RECT 151.430 0.000 151.710 4.000 ;
    END
  END key[49]
  PIN key[4]
    DIRECTION INPUT ;
    USE SIGNAL ;
    ANTENNAGATEAREA 0.213000 ;
    PORT
      LAYER met2 ;
        RECT 47.930 0.000 48.210 4.000 ;
    END
  END key[4]
  PIN key[50]
    DIRECTION INPUT ;
    USE SIGNAL ;
    ANTENNAGATEAREA 0.196500 ;
    PORT
      LAYER met2 ;
        RECT 153.730 0.000 154.010 4.000 ;
    END
  END key[50]
  PIN key[51]
    DIRECTION INPUT ;
    USE SIGNAL ;
    ANTENNAGATEAREA 0.213000 ;
    PORT
      LAYER met2 ;
        RECT 156.030 0.000 156.310 4.000 ;
    END
  END key[51]
  PIN key[52]
    DIRECTION INPUT ;
    USE SIGNAL ;
    ANTENNAGATEAREA 0.213000 ;
    PORT
      LAYER met2 ;
        RECT 158.330 0.000 158.610 4.000 ;
    END
  END key[52]
  PIN key[53]
    DIRECTION INPUT ;
    USE SIGNAL ;
    ANTENNAGATEAREA 0.159000 ;
    PORT
      LAYER met2 ;
        RECT 160.630 0.000 160.910 4.000 ;
    END
  END key[53]
  PIN key[54]
    DIRECTION INPUT ;
    USE SIGNAL ;
    ANTENNAGATEAREA 0.159000 ;
    PORT
      LAYER met2 ;
        RECT 162.930 0.000 163.210 4.000 ;
    END
  END key[54]
  PIN key[55]
    DIRECTION INPUT ;
    USE SIGNAL ;
    ANTENNAGATEAREA 0.159000 ;
    PORT
      LAYER met2 ;
        RECT 165.230 0.000 165.510 4.000 ;
    END
  END key[55]
  PIN key[56]
    DIRECTION INPUT ;
    USE SIGNAL ;
    ANTENNAGATEAREA 0.213000 ;
    PORT
      LAYER met2 ;
        RECT 167.530 0.000 167.810 4.000 ;
    END
  END key[56]
  PIN key[57]
    DIRECTION INPUT ;
    USE SIGNAL ;
    ANTENNAGATEAREA 0.159000 ;
    PORT
      LAYER met2 ;
        RECT 169.830 0.000 170.110 4.000 ;
    END
  END key[57]
  PIN key[58]
    DIRECTION INPUT ;
    USE SIGNAL ;
    ANTENNAGATEAREA 0.159000 ;
    PORT
      LAYER met2 ;
        RECT 172.130 0.000 172.410 4.000 ;
    END
  END key[58]
  PIN key[59]
    DIRECTION INPUT ;
    USE SIGNAL ;
    ANTENNAGATEAREA 0.213000 ;
    PORT
      LAYER met2 ;
        RECT 174.430 0.000 174.710 4.000 ;
    END
  END key[59]
  PIN key[5]
    DIRECTION INPUT ;
    USE SIGNAL ;
    ANTENNAGATEAREA 0.213000 ;
    PORT
      LAYER met2 ;
        RECT 50.230 0.000 50.510 4.000 ;
    END
  END key[5]
  PIN key[60]
    DIRECTION INPUT ;
    USE SIGNAL ;
    ANTENNAGATEAREA 0.213000 ;
    PORT
      LAYER met2 ;
        RECT 176.730 0.000 177.010 4.000 ;
    END
  END key[60]
  PIN key[61]
    DIRECTION INPUT ;
    USE SIGNAL ;
    ANTENNAGATEAREA 0.159000 ;
    PORT
      LAYER met2 ;
        RECT 179.030 0.000 179.310 4.000 ;
    END
  END key[61]
  PIN key[62]
    DIRECTION INPUT ;
    USE SIGNAL ;
    ANTENNAGATEAREA 0.159000 ;
    PORT
      LAYER met2 ;
        RECT 181.330 0.000 181.610 4.000 ;
    END
  END key[62]
  PIN key[63]
    DIRECTION INPUT ;
    USE SIGNAL ;
    ANTENNAGATEAREA 0.213000 ;
    PORT
      LAYER met2 ;
        RECT 183.630 0.000 183.910 4.000 ;
    END
  END key[63]
  PIN key[64]
    DIRECTION INPUT ;
    USE SIGNAL ;
    ANTENNAGATEAREA 0.213000 ;
    PORT
      LAYER met2 ;
        RECT 185.930 0.000 186.210 4.000 ;
    END
  END key[64]
  PIN key[65]
    DIRECTION INPUT ;
    USE SIGNAL ;
    ANTENNAGATEAREA 0.196500 ;
    PORT
      LAYER met2 ;
        RECT 188.230 0.000 188.510 4.000 ;
    END
  END key[65]
  PIN key[66]
    DIRECTION INPUT ;
    USE SIGNAL ;
    ANTENNAGATEAREA 0.213000 ;
    PORT
      LAYER met2 ;
        RECT 190.530 0.000 190.810 4.000 ;
    END
  END key[66]
  PIN key[67]
    DIRECTION INPUT ;
    USE SIGNAL ;
    ANTENNAGATEAREA 0.196500 ;
    PORT
      LAYER met2 ;
        RECT 192.830 0.000 193.110 4.000 ;
    END
  END key[67]
  PIN key[68]
    DIRECTION INPUT ;
    USE SIGNAL ;
    ANTENNAGATEAREA 0.196500 ;
    PORT
      LAYER met2 ;
        RECT 195.130 0.000 195.410 4.000 ;
    END
  END key[68]
  PIN key[69]
    DIRECTION INPUT ;
    USE SIGNAL ;
    ANTENNAGATEAREA 0.213000 ;
    PORT
      LAYER met2 ;
        RECT 197.430 0.000 197.710 4.000 ;
    END
  END key[69]
  PIN key[6]
    DIRECTION INPUT ;
    USE SIGNAL ;
    ANTENNAGATEAREA 0.213000 ;
    PORT
      LAYER met2 ;
        RECT 52.530 0.000 52.810 4.000 ;
    END
  END key[6]
  PIN key[70]
    DIRECTION INPUT ;
    USE SIGNAL ;
    ANTENNAGATEAREA 0.196500 ;
    PORT
      LAYER met2 ;
        RECT 199.730 0.000 200.010 4.000 ;
    END
  END key[70]
  PIN key[71]
    DIRECTION INPUT ;
    USE SIGNAL ;
    ANTENNAGATEAREA 0.159000 ;
    PORT
      LAYER met2 ;
        RECT 202.030 0.000 202.310 4.000 ;
    END
  END key[71]
  PIN key[72]
    DIRECTION INPUT ;
    USE SIGNAL ;
    ANTENNAGATEAREA 0.196500 ;
    PORT
      LAYER met2 ;
        RECT 204.330 0.000 204.610 4.000 ;
    END
  END key[72]
  PIN key[73]
    DIRECTION INPUT ;
    USE SIGNAL ;
    ANTENNAGATEAREA 0.159000 ;
    PORT
      LAYER met2 ;
        RECT 206.630 0.000 206.910 4.000 ;
    END
  END key[73]
  PIN key[74]
    DIRECTION INPUT ;
    USE SIGNAL ;
    ANTENNAGATEAREA 0.213000 ;
    PORT
      LAYER met2 ;
        RECT 208.930 0.000 209.210 4.000 ;
    END
  END key[74]
  PIN key[75]
    DIRECTION INPUT ;
    USE SIGNAL ;
    ANTENNAGATEAREA 0.213000 ;
    PORT
      LAYER met2 ;
        RECT 211.230 0.000 211.510 4.000 ;
    END
  END key[75]
  PIN key[76]
    DIRECTION INPUT ;
    USE SIGNAL ;
    ANTENNAGATEAREA 0.196500 ;
    PORT
      LAYER met2 ;
        RECT 213.530 0.000 213.810 4.000 ;
    END
  END key[76]
  PIN key[77]
    DIRECTION INPUT ;
    USE SIGNAL ;
    ANTENNAGATEAREA 0.126000 ;
    PORT
      LAYER met2 ;
        RECT 215.830 0.000 216.110 4.000 ;
    END
  END key[77]
  PIN key[78]
    DIRECTION INPUT ;
    USE SIGNAL ;
    ANTENNAGATEAREA 0.196500 ;
    PORT
      LAYER met2 ;
        RECT 218.130 0.000 218.410 4.000 ;
    END
  END key[78]
  PIN key[79]
    DIRECTION INPUT ;
    USE SIGNAL ;
    ANTENNAGATEAREA 0.159000 ;
    PORT
      LAYER met2 ;
        RECT 220.430 0.000 220.710 4.000 ;
    END
  END key[79]
  PIN key[7]
    DIRECTION INPUT ;
    USE SIGNAL ;
    ANTENNAGATEAREA 0.213000 ;
    PORT
      LAYER met2 ;
        RECT 54.830 0.000 55.110 4.000 ;
    END
  END key[7]
  PIN key[80]
    DIRECTION INPUT ;
    USE SIGNAL ;
    ANTENNAGATEAREA 0.159000 ;
    PORT
      LAYER met2 ;
        RECT 222.730 0.000 223.010 4.000 ;
    END
  END key[80]
  PIN key[81]
    DIRECTION INPUT ;
    USE SIGNAL ;
    ANTENNAGATEAREA 0.196500 ;
    PORT
      LAYER met2 ;
        RECT 225.030 0.000 225.310 4.000 ;
    END
  END key[81]
  PIN key[82]
    DIRECTION INPUT ;
    USE SIGNAL ;
    ANTENNAGATEAREA 0.159000 ;
    PORT
      LAYER met2 ;
        RECT 227.330 0.000 227.610 4.000 ;
    END
  END key[82]
  PIN key[83]
    DIRECTION INPUT ;
    USE SIGNAL ;
    ANTENNAGATEAREA 0.213000 ;
    PORT
      LAYER met2 ;
        RECT 229.630 0.000 229.910 4.000 ;
    END
  END key[83]
  PIN key[84]
    DIRECTION INPUT ;
    USE SIGNAL ;
    ANTENNAGATEAREA 0.159000 ;
    PORT
      LAYER met2 ;
        RECT 231.930 0.000 232.210 4.000 ;
    END
  END key[84]
  PIN key[85]
    DIRECTION INPUT ;
    USE SIGNAL ;
    ANTENNAGATEAREA 0.213000 ;
    PORT
      LAYER met2 ;
        RECT 234.230 0.000 234.510 4.000 ;
    END
  END key[85]
  PIN key[86]
    DIRECTION INPUT ;
    USE SIGNAL ;
    ANTENNAGATEAREA 0.213000 ;
    PORT
      LAYER met2 ;
        RECT 236.530 0.000 236.810 4.000 ;
    END
  END key[86]
  PIN key[87]
    DIRECTION INPUT ;
    USE SIGNAL ;
    ANTENNAGATEAREA 0.213000 ;
    PORT
      LAYER met2 ;
        RECT 238.830 0.000 239.110 4.000 ;
    END
  END key[87]
  PIN key[88]
    DIRECTION INPUT ;
    USE SIGNAL ;
    ANTENNAGATEAREA 0.196500 ;
    PORT
      LAYER met2 ;
        RECT 241.130 0.000 241.410 4.000 ;
    END
  END key[88]
  PIN key[89]
    DIRECTION INPUT ;
    USE SIGNAL ;
    ANTENNAGATEAREA 0.159000 ;
    PORT
      LAYER met2 ;
        RECT 243.430 0.000 243.710 4.000 ;
    END
  END key[89]
  PIN key[8]
    DIRECTION INPUT ;
    USE SIGNAL ;
    ANTENNAGATEAREA 0.213000 ;
    PORT
      LAYER met2 ;
        RECT 57.130 0.000 57.410 4.000 ;
    END
  END key[8]
  PIN key[90]
    DIRECTION INPUT ;
    USE SIGNAL ;
    ANTENNAGATEAREA 0.213000 ;
    PORT
      LAYER met2 ;
        RECT 245.730 0.000 246.010 4.000 ;
    END
  END key[90]
  PIN key[91]
    DIRECTION INPUT ;
    USE SIGNAL ;
    ANTENNAGATEAREA 0.159000 ;
    PORT
      LAYER met2 ;
        RECT 248.030 0.000 248.310 4.000 ;
    END
  END key[91]
  PIN key[92]
    DIRECTION INPUT ;
    USE SIGNAL ;
    ANTENNAGATEAREA 0.159000 ;
    PORT
      LAYER met2 ;
        RECT 250.330 0.000 250.610 4.000 ;
    END
  END key[92]
  PIN key[93]
    DIRECTION INPUT ;
    USE SIGNAL ;
    ANTENNAGATEAREA 0.213000 ;
    PORT
      LAYER met2 ;
        RECT 252.630 0.000 252.910 4.000 ;
    END
  END key[93]
  PIN key[94]
    DIRECTION INPUT ;
    USE SIGNAL ;
    ANTENNAGATEAREA 0.159000 ;
    PORT
      LAYER met2 ;
        RECT 254.930 0.000 255.210 4.000 ;
    END
  END key[94]
  PIN key[95]
    DIRECTION INPUT ;
    USE SIGNAL ;
    ANTENNAGATEAREA 0.159000 ;
    PORT
      LAYER met2 ;
        RECT 257.230 0.000 257.510 4.000 ;
    END
  END key[95]
  PIN key[96]
    DIRECTION INPUT ;
    USE SIGNAL ;
    ANTENNAGATEAREA 0.196500 ;
    PORT
      LAYER met2 ;
        RECT 259.530 0.000 259.810 4.000 ;
    END
  END key[96]
  PIN key[97]
    DIRECTION INPUT ;
    USE SIGNAL ;
    ANTENNAGATEAREA 0.196500 ;
    PORT
      LAYER met2 ;
        RECT 261.830 0.000 262.110 4.000 ;
    END
  END key[97]
  PIN key[98]
    DIRECTION INPUT ;
    USE SIGNAL ;
    ANTENNAGATEAREA 0.126000 ;
    PORT
      LAYER met2 ;
        RECT 264.130 0.000 264.410 4.000 ;
    END
  END key[98]
  PIN key[99]
    DIRECTION INPUT ;
    USE SIGNAL ;
    ANTENNAGATEAREA 0.196500 ;
    PORT
      LAYER met2 ;
        RECT 266.430 0.000 266.710 4.000 ;
    END
  END key[99]
  PIN key[9]
    DIRECTION INPUT ;
    USE SIGNAL ;
    ANTENNAGATEAREA 0.213000 ;
    PORT
      LAYER met2 ;
        RECT 59.430 0.000 59.710 4.000 ;
    END
  END key[9]
  PIN keylen
    DIRECTION INPUT ;
    USE SIGNAL ;
    ANTENNAGATEAREA 0.852000 ;
    PORT
      LAYER met2 ;
        RECT 538.750 671.155 539.030 675.155 ;
    END
  END keylen
  PIN next
    DIRECTION INPUT ;
    USE SIGNAL ;
    ANTENNAGATEAREA 0.213000 ;
    PORT
      LAYER met2 ;
        RECT 373.150 671.155 373.430 675.155 ;
    END
  END next
  PIN ready
    DIRECTION OUTPUT ;
    USE SIGNAL ;
    ANTENNADIFFAREA 0.340600 ;
    PORT
      LAYER met2 ;
        RECT 455.950 671.155 456.230 675.155 ;
    END
  END ready
  PIN reset_n
    DIRECTION INPUT ;
    USE SIGNAL ;
    ANTENNAGATEAREA 0.213000 ;
    PORT
      LAYER met2 ;
        RECT 124.750 671.155 125.030 675.155 ;
    END
  END reset_n
  PIN result[0]
    DIRECTION OUTPUT ;
    USE SIGNAL ;
    ANTENNADIFFAREA 0.340600 ;
    PORT
      LAYER met3 ;
        RECT 0.000 77.560 4.000 78.160 ;
    END
  END result[0]
  PIN result[100]
    DIRECTION OUTPUT ;
    USE SIGNAL ;
    ANTENNADIFFAREA 0.340600 ;
    PORT
      LAYER met3 ;
        RECT 0.000 485.560 4.000 486.160 ;
    END
  END result[100]
  PIN result[101]
    DIRECTION OUTPUT ;
    USE SIGNAL ;
    ANTENNADIFFAREA 0.340600 ;
    PORT
      LAYER met3 ;
        RECT 0.000 489.640 4.000 490.240 ;
    END
  END result[101]
  PIN result[102]
    DIRECTION OUTPUT ;
    USE SIGNAL ;
    ANTENNADIFFAREA 0.340600 ;
    PORT
      LAYER met3 ;
        RECT 0.000 493.720 4.000 494.320 ;
    END
  END result[102]
  PIN result[103]
    DIRECTION OUTPUT ;
    USE SIGNAL ;
    ANTENNADIFFAREA 0.340600 ;
    PORT
      LAYER met3 ;
        RECT 0.000 497.800 4.000 498.400 ;
    END
  END result[103]
  PIN result[104]
    DIRECTION OUTPUT ;
    USE SIGNAL ;
    ANTENNADIFFAREA 0.340600 ;
    PORT
      LAYER met3 ;
        RECT 0.000 501.880 4.000 502.480 ;
    END
  END result[104]
  PIN result[105]
    DIRECTION OUTPUT ;
    USE SIGNAL ;
    ANTENNADIFFAREA 0.340600 ;
    PORT
      LAYER met3 ;
        RECT 0.000 505.960 4.000 506.560 ;
    END
  END result[105]
  PIN result[106]
    DIRECTION OUTPUT ;
    USE SIGNAL ;
    ANTENNADIFFAREA 0.340600 ;
    PORT
      LAYER met3 ;
        RECT 0.000 510.040 4.000 510.640 ;
    END
  END result[106]
  PIN result[107]
    DIRECTION OUTPUT ;
    USE SIGNAL ;
    ANTENNADIFFAREA 0.340600 ;
    PORT
      LAYER met3 ;
        RECT 0.000 514.120 4.000 514.720 ;
    END
  END result[107]
  PIN result[108]
    DIRECTION OUTPUT ;
    USE SIGNAL ;
    ANTENNADIFFAREA 0.340600 ;
    PORT
      LAYER met3 ;
        RECT 0.000 518.200 4.000 518.800 ;
    END
  END result[108]
  PIN result[109]
    DIRECTION OUTPUT ;
    USE SIGNAL ;
    ANTENNADIFFAREA 0.340600 ;
    PORT
      LAYER met3 ;
        RECT 0.000 522.280 4.000 522.880 ;
    END
  END result[109]
  PIN result[10]
    DIRECTION OUTPUT ;
    USE SIGNAL ;
    ANTENNADIFFAREA 0.340600 ;
    PORT
      LAYER met3 ;
        RECT 0.000 118.360 4.000 118.960 ;
    END
  END result[10]
  PIN result[110]
    DIRECTION OUTPUT ;
    USE SIGNAL ;
    ANTENNADIFFAREA 0.340600 ;
    PORT
      LAYER met3 ;
        RECT 0.000 526.360 4.000 526.960 ;
    END
  END result[110]
  PIN result[111]
    DIRECTION OUTPUT ;
    USE SIGNAL ;
    ANTENNADIFFAREA 0.340600 ;
    PORT
      LAYER met3 ;
        RECT 0.000 530.440 4.000 531.040 ;
    END
  END result[111]
  PIN result[112]
    DIRECTION OUTPUT ;
    USE SIGNAL ;
    ANTENNADIFFAREA 0.340600 ;
    PORT
      LAYER met3 ;
        RECT 0.000 534.520 4.000 535.120 ;
    END
  END result[112]
  PIN result[113]
    DIRECTION OUTPUT ;
    USE SIGNAL ;
    ANTENNADIFFAREA 0.340600 ;
    PORT
      LAYER met3 ;
        RECT 0.000 538.600 4.000 539.200 ;
    END
  END result[113]
  PIN result[114]
    DIRECTION OUTPUT ;
    USE SIGNAL ;
    ANTENNADIFFAREA 0.340600 ;
    PORT
      LAYER met3 ;
        RECT 0.000 542.680 4.000 543.280 ;
    END
  END result[114]
  PIN result[115]
    DIRECTION OUTPUT ;
    USE SIGNAL ;
    ANTENNADIFFAREA 0.340600 ;
    PORT
      LAYER met3 ;
        RECT 0.000 546.760 4.000 547.360 ;
    END
  END result[115]
  PIN result[116]
    DIRECTION OUTPUT ;
    USE SIGNAL ;
    ANTENNADIFFAREA 0.340600 ;
    PORT
      LAYER met3 ;
        RECT 0.000 550.840 4.000 551.440 ;
    END
  END result[116]
  PIN result[117]
    DIRECTION OUTPUT ;
    USE SIGNAL ;
    ANTENNADIFFAREA 0.340600 ;
    PORT
      LAYER met3 ;
        RECT 0.000 554.920 4.000 555.520 ;
    END
  END result[117]
  PIN result[118]
    DIRECTION OUTPUT ;
    USE SIGNAL ;
    ANTENNADIFFAREA 0.340600 ;
    PORT
      LAYER met3 ;
        RECT 0.000 559.000 4.000 559.600 ;
    END
  END result[118]
  PIN result[119]
    DIRECTION OUTPUT ;
    USE SIGNAL ;
    ANTENNADIFFAREA 0.340600 ;
    PORT
      LAYER met3 ;
        RECT 0.000 563.080 4.000 563.680 ;
    END
  END result[119]
  PIN result[11]
    DIRECTION OUTPUT ;
    USE SIGNAL ;
    ANTENNADIFFAREA 0.340600 ;
    PORT
      LAYER met3 ;
        RECT 0.000 122.440 4.000 123.040 ;
    END
  END result[11]
  PIN result[120]
    DIRECTION OUTPUT ;
    USE SIGNAL ;
    ANTENNADIFFAREA 0.340600 ;
    PORT
      LAYER met3 ;
        RECT 0.000 567.160 4.000 567.760 ;
    END
  END result[120]
  PIN result[121]
    DIRECTION OUTPUT ;
    USE SIGNAL ;
    ANTENNADIFFAREA 0.340600 ;
    PORT
      LAYER met3 ;
        RECT 0.000 571.240 4.000 571.840 ;
    END
  END result[121]
  PIN result[122]
    DIRECTION OUTPUT ;
    USE SIGNAL ;
    ANTENNADIFFAREA 0.340600 ;
    PORT
      LAYER met3 ;
        RECT 0.000 575.320 4.000 575.920 ;
    END
  END result[122]
  PIN result[123]
    DIRECTION OUTPUT ;
    USE SIGNAL ;
    ANTENNADIFFAREA 0.340600 ;
    PORT
      LAYER met3 ;
        RECT 0.000 579.400 4.000 580.000 ;
    END
  END result[123]
  PIN result[124]
    DIRECTION OUTPUT ;
    USE SIGNAL ;
    ANTENNADIFFAREA 0.340600 ;
    PORT
      LAYER met3 ;
        RECT 0.000 583.480 4.000 584.080 ;
    END
  END result[124]
  PIN result[125]
    DIRECTION OUTPUT ;
    USE SIGNAL ;
    ANTENNADIFFAREA 0.340600 ;
    PORT
      LAYER met3 ;
        RECT 0.000 587.560 4.000 588.160 ;
    END
  END result[125]
  PIN result[126]
    DIRECTION OUTPUT ;
    USE SIGNAL ;
    ANTENNADIFFAREA 0.340600 ;
    PORT
      LAYER met3 ;
        RECT 0.000 591.640 4.000 592.240 ;
    END
  END result[126]
  PIN result[127]
    DIRECTION OUTPUT ;
    USE SIGNAL ;
    ANTENNADIFFAREA 0.340600 ;
    PORT
      LAYER met3 ;
        RECT 0.000 595.720 4.000 596.320 ;
    END
  END result[127]
  PIN result[12]
    DIRECTION OUTPUT ;
    USE SIGNAL ;
    ANTENNADIFFAREA 0.340600 ;
    PORT
      LAYER met3 ;
        RECT 0.000 126.520 4.000 127.120 ;
    END
  END result[12]
  PIN result[13]
    DIRECTION OUTPUT ;
    USE SIGNAL ;
    ANTENNADIFFAREA 0.340600 ;
    PORT
      LAYER met3 ;
        RECT 0.000 130.600 4.000 131.200 ;
    END
  END result[13]
  PIN result[14]
    DIRECTION OUTPUT ;
    USE SIGNAL ;
    ANTENNADIFFAREA 0.340600 ;
    PORT
      LAYER met3 ;
        RECT 0.000 134.680 4.000 135.280 ;
    END
  END result[14]
  PIN result[15]
    DIRECTION OUTPUT ;
    USE SIGNAL ;
    ANTENNADIFFAREA 0.340600 ;
    PORT
      LAYER met3 ;
        RECT 0.000 138.760 4.000 139.360 ;
    END
  END result[15]
  PIN result[16]
    DIRECTION OUTPUT ;
    USE SIGNAL ;
    ANTENNADIFFAREA 0.340600 ;
    PORT
      LAYER met3 ;
        RECT 0.000 142.840 4.000 143.440 ;
    END
  END result[16]
  PIN result[17]
    DIRECTION OUTPUT ;
    USE SIGNAL ;
    ANTENNADIFFAREA 0.340600 ;
    PORT
      LAYER met3 ;
        RECT 0.000 146.920 4.000 147.520 ;
    END
  END result[17]
  PIN result[18]
    DIRECTION OUTPUT ;
    USE SIGNAL ;
    ANTENNADIFFAREA 0.340600 ;
    PORT
      LAYER met3 ;
        RECT 0.000 151.000 4.000 151.600 ;
    END
  END result[18]
  PIN result[19]
    DIRECTION OUTPUT ;
    USE SIGNAL ;
    ANTENNADIFFAREA 0.340600 ;
    PORT
      LAYER met3 ;
        RECT 0.000 155.080 4.000 155.680 ;
    END
  END result[19]
  PIN result[1]
    DIRECTION OUTPUT ;
    USE SIGNAL ;
    ANTENNADIFFAREA 0.340600 ;
    PORT
      LAYER met3 ;
        RECT 0.000 81.640 4.000 82.240 ;
    END
  END result[1]
  PIN result[20]
    DIRECTION OUTPUT ;
    USE SIGNAL ;
    ANTENNADIFFAREA 0.340600 ;
    PORT
      LAYER met3 ;
        RECT 0.000 159.160 4.000 159.760 ;
    END
  END result[20]
  PIN result[21]
    DIRECTION OUTPUT ;
    USE SIGNAL ;
    ANTENNADIFFAREA 0.340600 ;
    PORT
      LAYER met3 ;
        RECT 0.000 163.240 4.000 163.840 ;
    END
  END result[21]
  PIN result[22]
    DIRECTION OUTPUT ;
    USE SIGNAL ;
    ANTENNADIFFAREA 0.340600 ;
    PORT
      LAYER met3 ;
        RECT 0.000 167.320 4.000 167.920 ;
    END
  END result[22]
  PIN result[23]
    DIRECTION OUTPUT ;
    USE SIGNAL ;
    ANTENNADIFFAREA 0.340600 ;
    PORT
      LAYER met3 ;
        RECT 0.000 171.400 4.000 172.000 ;
    END
  END result[23]
  PIN result[24]
    DIRECTION OUTPUT ;
    USE SIGNAL ;
    ANTENNADIFFAREA 0.340600 ;
    PORT
      LAYER met3 ;
        RECT 0.000 175.480 4.000 176.080 ;
    END
  END result[24]
  PIN result[25]
    DIRECTION OUTPUT ;
    USE SIGNAL ;
    ANTENNADIFFAREA 0.340600 ;
    PORT
      LAYER met3 ;
        RECT 0.000 179.560 4.000 180.160 ;
    END
  END result[25]
  PIN result[26]
    DIRECTION OUTPUT ;
    USE SIGNAL ;
    ANTENNADIFFAREA 0.340600 ;
    PORT
      LAYER met3 ;
        RECT 0.000 183.640 4.000 184.240 ;
    END
  END result[26]
  PIN result[27]
    DIRECTION OUTPUT ;
    USE SIGNAL ;
    ANTENNADIFFAREA 0.340600 ;
    PORT
      LAYER met3 ;
        RECT 0.000 187.720 4.000 188.320 ;
    END
  END result[27]
  PIN result[28]
    DIRECTION OUTPUT ;
    USE SIGNAL ;
    ANTENNADIFFAREA 0.340600 ;
    PORT
      LAYER met3 ;
        RECT 0.000 191.800 4.000 192.400 ;
    END
  END result[28]
  PIN result[29]
    DIRECTION OUTPUT ;
    USE SIGNAL ;
    ANTENNADIFFAREA 0.340600 ;
    PORT
      LAYER met3 ;
        RECT 0.000 195.880 4.000 196.480 ;
    END
  END result[29]
  PIN result[2]
    DIRECTION OUTPUT ;
    USE SIGNAL ;
    ANTENNADIFFAREA 0.340600 ;
    PORT
      LAYER met3 ;
        RECT 0.000 85.720 4.000 86.320 ;
    END
  END result[2]
  PIN result[30]
    DIRECTION OUTPUT ;
    USE SIGNAL ;
    ANTENNADIFFAREA 0.340600 ;
    PORT
      LAYER met3 ;
        RECT 0.000 199.960 4.000 200.560 ;
    END
  END result[30]
  PIN result[31]
    DIRECTION OUTPUT ;
    USE SIGNAL ;
    ANTENNADIFFAREA 0.340600 ;
    PORT
      LAYER met3 ;
        RECT 0.000 204.040 4.000 204.640 ;
    END
  END result[31]
  PIN result[32]
    DIRECTION OUTPUT ;
    USE SIGNAL ;
    ANTENNADIFFAREA 0.340600 ;
    PORT
      LAYER met3 ;
        RECT 0.000 208.120 4.000 208.720 ;
    END
  END result[32]
  PIN result[33]
    DIRECTION OUTPUT ;
    USE SIGNAL ;
    ANTENNADIFFAREA 0.340600 ;
    PORT
      LAYER met3 ;
        RECT 0.000 212.200 4.000 212.800 ;
    END
  END result[33]
  PIN result[34]
    DIRECTION OUTPUT ;
    USE SIGNAL ;
    ANTENNADIFFAREA 0.340600 ;
    PORT
      LAYER met3 ;
        RECT 0.000 216.280 4.000 216.880 ;
    END
  END result[34]
  PIN result[35]
    DIRECTION OUTPUT ;
    USE SIGNAL ;
    ANTENNADIFFAREA 0.340600 ;
    PORT
      LAYER met3 ;
        RECT 0.000 220.360 4.000 220.960 ;
    END
  END result[35]
  PIN result[36]
    DIRECTION OUTPUT ;
    USE SIGNAL ;
    ANTENNADIFFAREA 0.340600 ;
    PORT
      LAYER met3 ;
        RECT 0.000 224.440 4.000 225.040 ;
    END
  END result[36]
  PIN result[37]
    DIRECTION OUTPUT ;
    USE SIGNAL ;
    ANTENNADIFFAREA 0.340600 ;
    PORT
      LAYER met3 ;
        RECT 0.000 228.520 4.000 229.120 ;
    END
  END result[37]
  PIN result[38]
    DIRECTION OUTPUT ;
    USE SIGNAL ;
    ANTENNADIFFAREA 0.340600 ;
    PORT
      LAYER met3 ;
        RECT 0.000 232.600 4.000 233.200 ;
    END
  END result[38]
  PIN result[39]
    DIRECTION OUTPUT ;
    USE SIGNAL ;
    ANTENNADIFFAREA 0.340600 ;
    PORT
      LAYER met3 ;
        RECT 0.000 236.680 4.000 237.280 ;
    END
  END result[39]
  PIN result[3]
    DIRECTION OUTPUT ;
    USE SIGNAL ;
    ANTENNADIFFAREA 0.340600 ;
    PORT
      LAYER met3 ;
        RECT 0.000 89.800 4.000 90.400 ;
    END
  END result[3]
  PIN result[40]
    DIRECTION OUTPUT ;
    USE SIGNAL ;
    ANTENNADIFFAREA 0.340600 ;
    PORT
      LAYER met3 ;
        RECT 0.000 240.760 4.000 241.360 ;
    END
  END result[40]
  PIN result[41]
    DIRECTION OUTPUT ;
    USE SIGNAL ;
    ANTENNADIFFAREA 0.340600 ;
    PORT
      LAYER met3 ;
        RECT 0.000 244.840 4.000 245.440 ;
    END
  END result[41]
  PIN result[42]
    DIRECTION OUTPUT ;
    USE SIGNAL ;
    ANTENNADIFFAREA 0.340600 ;
    PORT
      LAYER met3 ;
        RECT 0.000 248.920 4.000 249.520 ;
    END
  END result[42]
  PIN result[43]
    DIRECTION OUTPUT ;
    USE SIGNAL ;
    ANTENNADIFFAREA 0.340600 ;
    PORT
      LAYER met3 ;
        RECT 0.000 253.000 4.000 253.600 ;
    END
  END result[43]
  PIN result[44]
    DIRECTION OUTPUT ;
    USE SIGNAL ;
    ANTENNADIFFAREA 0.340600 ;
    PORT
      LAYER met3 ;
        RECT 0.000 257.080 4.000 257.680 ;
    END
  END result[44]
  PIN result[45]
    DIRECTION OUTPUT ;
    USE SIGNAL ;
    ANTENNADIFFAREA 0.340600 ;
    PORT
      LAYER met3 ;
        RECT 0.000 261.160 4.000 261.760 ;
    END
  END result[45]
  PIN result[46]
    DIRECTION OUTPUT ;
    USE SIGNAL ;
    ANTENNADIFFAREA 0.340600 ;
    PORT
      LAYER met3 ;
        RECT 0.000 265.240 4.000 265.840 ;
    END
  END result[46]
  PIN result[47]
    DIRECTION OUTPUT ;
    USE SIGNAL ;
    ANTENNADIFFAREA 0.340600 ;
    PORT
      LAYER met3 ;
        RECT 0.000 269.320 4.000 269.920 ;
    END
  END result[47]
  PIN result[48]
    DIRECTION OUTPUT ;
    USE SIGNAL ;
    ANTENNADIFFAREA 0.340600 ;
    PORT
      LAYER met3 ;
        RECT 0.000 273.400 4.000 274.000 ;
    END
  END result[48]
  PIN result[49]
    DIRECTION OUTPUT ;
    USE SIGNAL ;
    ANTENNADIFFAREA 0.340600 ;
    PORT
      LAYER met3 ;
        RECT 0.000 277.480 4.000 278.080 ;
    END
  END result[49]
  PIN result[4]
    DIRECTION OUTPUT ;
    USE SIGNAL ;
    ANTENNADIFFAREA 0.340600 ;
    PORT
      LAYER met3 ;
        RECT 0.000 93.880 4.000 94.480 ;
    END
  END result[4]
  PIN result[50]
    DIRECTION OUTPUT ;
    USE SIGNAL ;
    ANTENNADIFFAREA 0.340600 ;
    PORT
      LAYER met3 ;
        RECT 0.000 281.560 4.000 282.160 ;
    END
  END result[50]
  PIN result[51]
    DIRECTION OUTPUT ;
    USE SIGNAL ;
    ANTENNADIFFAREA 0.340600 ;
    PORT
      LAYER met3 ;
        RECT 0.000 285.640 4.000 286.240 ;
    END
  END result[51]
  PIN result[52]
    DIRECTION OUTPUT ;
    USE SIGNAL ;
    ANTENNADIFFAREA 0.340600 ;
    PORT
      LAYER met3 ;
        RECT 0.000 289.720 4.000 290.320 ;
    END
  END result[52]
  PIN result[53]
    DIRECTION OUTPUT ;
    USE SIGNAL ;
    ANTENNADIFFAREA 0.340600 ;
    PORT
      LAYER met3 ;
        RECT 0.000 293.800 4.000 294.400 ;
    END
  END result[53]
  PIN result[54]
    DIRECTION OUTPUT ;
    USE SIGNAL ;
    ANTENNADIFFAREA 0.340600 ;
    PORT
      LAYER met3 ;
        RECT 0.000 297.880 4.000 298.480 ;
    END
  END result[54]
  PIN result[55]
    DIRECTION OUTPUT ;
    USE SIGNAL ;
    ANTENNADIFFAREA 0.340600 ;
    PORT
      LAYER met3 ;
        RECT 0.000 301.960 4.000 302.560 ;
    END
  END result[55]
  PIN result[56]
    DIRECTION OUTPUT ;
    USE SIGNAL ;
    ANTENNADIFFAREA 0.340600 ;
    PORT
      LAYER met3 ;
        RECT 0.000 306.040 4.000 306.640 ;
    END
  END result[56]
  PIN result[57]
    DIRECTION OUTPUT ;
    USE SIGNAL ;
    ANTENNADIFFAREA 0.340600 ;
    PORT
      LAYER met3 ;
        RECT 0.000 310.120 4.000 310.720 ;
    END
  END result[57]
  PIN result[58]
    DIRECTION OUTPUT ;
    USE SIGNAL ;
    ANTENNADIFFAREA 0.340600 ;
    PORT
      LAYER met3 ;
        RECT 0.000 314.200 4.000 314.800 ;
    END
  END result[58]
  PIN result[59]
    DIRECTION OUTPUT ;
    USE SIGNAL ;
    ANTENNADIFFAREA 0.340600 ;
    PORT
      LAYER met3 ;
        RECT 0.000 318.280 4.000 318.880 ;
    END
  END result[59]
  PIN result[5]
    DIRECTION OUTPUT ;
    USE SIGNAL ;
    ANTENNADIFFAREA 0.340600 ;
    PORT
      LAYER met3 ;
        RECT 0.000 97.960 4.000 98.560 ;
    END
  END result[5]
  PIN result[60]
    DIRECTION OUTPUT ;
    USE SIGNAL ;
    ANTENNADIFFAREA 0.340600 ;
    PORT
      LAYER met3 ;
        RECT 0.000 322.360 4.000 322.960 ;
    END
  END result[60]
  PIN result[61]
    DIRECTION OUTPUT ;
    USE SIGNAL ;
    ANTENNADIFFAREA 0.340600 ;
    PORT
      LAYER met3 ;
        RECT 0.000 326.440 4.000 327.040 ;
    END
  END result[61]
  PIN result[62]
    DIRECTION OUTPUT ;
    USE SIGNAL ;
    ANTENNADIFFAREA 0.340600 ;
    PORT
      LAYER met3 ;
        RECT 0.000 330.520 4.000 331.120 ;
    END
  END result[62]
  PIN result[63]
    DIRECTION OUTPUT ;
    USE SIGNAL ;
    ANTENNADIFFAREA 0.340600 ;
    PORT
      LAYER met3 ;
        RECT 0.000 334.600 4.000 335.200 ;
    END
  END result[63]
  PIN result[64]
    DIRECTION OUTPUT ;
    USE SIGNAL ;
    ANTENNADIFFAREA 0.340600 ;
    PORT
      LAYER met3 ;
        RECT 0.000 338.680 4.000 339.280 ;
    END
  END result[64]
  PIN result[65]
    DIRECTION OUTPUT ;
    USE SIGNAL ;
    ANTENNADIFFAREA 0.340600 ;
    PORT
      LAYER met3 ;
        RECT 0.000 342.760 4.000 343.360 ;
    END
  END result[65]
  PIN result[66]
    DIRECTION OUTPUT ;
    USE SIGNAL ;
    ANTENNADIFFAREA 0.340600 ;
    PORT
      LAYER met3 ;
        RECT 0.000 346.840 4.000 347.440 ;
    END
  END result[66]
  PIN result[67]
    DIRECTION OUTPUT ;
    USE SIGNAL ;
    ANTENNADIFFAREA 0.340600 ;
    PORT
      LAYER met3 ;
        RECT 0.000 350.920 4.000 351.520 ;
    END
  END result[67]
  PIN result[68]
    DIRECTION OUTPUT ;
    USE SIGNAL ;
    ANTENNADIFFAREA 0.340600 ;
    PORT
      LAYER met3 ;
        RECT 0.000 355.000 4.000 355.600 ;
    END
  END result[68]
  PIN result[69]
    DIRECTION OUTPUT ;
    USE SIGNAL ;
    ANTENNADIFFAREA 0.340600 ;
    PORT
      LAYER met3 ;
        RECT 0.000 359.080 4.000 359.680 ;
    END
  END result[69]
  PIN result[6]
    DIRECTION OUTPUT ;
    USE SIGNAL ;
    ANTENNADIFFAREA 0.340600 ;
    PORT
      LAYER met3 ;
        RECT 0.000 102.040 4.000 102.640 ;
    END
  END result[6]
  PIN result[70]
    DIRECTION OUTPUT ;
    USE SIGNAL ;
    ANTENNADIFFAREA 0.340600 ;
    PORT
      LAYER met3 ;
        RECT 0.000 363.160 4.000 363.760 ;
    END
  END result[70]
  PIN result[71]
    DIRECTION OUTPUT ;
    USE SIGNAL ;
    ANTENNADIFFAREA 0.340600 ;
    PORT
      LAYER met3 ;
        RECT 0.000 367.240 4.000 367.840 ;
    END
  END result[71]
  PIN result[72]
    DIRECTION OUTPUT ;
    USE SIGNAL ;
    ANTENNADIFFAREA 0.340600 ;
    PORT
      LAYER met3 ;
        RECT 0.000 371.320 4.000 371.920 ;
    END
  END result[72]
  PIN result[73]
    DIRECTION OUTPUT ;
    USE SIGNAL ;
    ANTENNADIFFAREA 0.340600 ;
    PORT
      LAYER met3 ;
        RECT 0.000 375.400 4.000 376.000 ;
    END
  END result[73]
  PIN result[74]
    DIRECTION OUTPUT ;
    USE SIGNAL ;
    ANTENNADIFFAREA 0.340600 ;
    PORT
      LAYER met3 ;
        RECT 0.000 379.480 4.000 380.080 ;
    END
  END result[74]
  PIN result[75]
    DIRECTION OUTPUT ;
    USE SIGNAL ;
    ANTENNADIFFAREA 0.340600 ;
    PORT
      LAYER met3 ;
        RECT 0.000 383.560 4.000 384.160 ;
    END
  END result[75]
  PIN result[76]
    DIRECTION OUTPUT ;
    USE SIGNAL ;
    ANTENNADIFFAREA 0.340600 ;
    PORT
      LAYER met3 ;
        RECT 0.000 387.640 4.000 388.240 ;
    END
  END result[76]
  PIN result[77]
    DIRECTION OUTPUT ;
    USE SIGNAL ;
    ANTENNADIFFAREA 0.340600 ;
    PORT
      LAYER met3 ;
        RECT 0.000 391.720 4.000 392.320 ;
    END
  END result[77]
  PIN result[78]
    DIRECTION OUTPUT ;
    USE SIGNAL ;
    ANTENNADIFFAREA 0.340600 ;
    PORT
      LAYER met3 ;
        RECT 0.000 395.800 4.000 396.400 ;
    END
  END result[78]
  PIN result[79]
    DIRECTION OUTPUT ;
    USE SIGNAL ;
    ANTENNADIFFAREA 0.340600 ;
    PORT
      LAYER met3 ;
        RECT 0.000 399.880 4.000 400.480 ;
    END
  END result[79]
  PIN result[7]
    DIRECTION OUTPUT ;
    USE SIGNAL ;
    ANTENNADIFFAREA 0.340600 ;
    PORT
      LAYER met3 ;
        RECT 0.000 106.120 4.000 106.720 ;
    END
  END result[7]
  PIN result[80]
    DIRECTION OUTPUT ;
    USE SIGNAL ;
    ANTENNADIFFAREA 0.340600 ;
    PORT
      LAYER met3 ;
        RECT 0.000 403.960 4.000 404.560 ;
    END
  END result[80]
  PIN result[81]
    DIRECTION OUTPUT ;
    USE SIGNAL ;
    ANTENNADIFFAREA 0.340600 ;
    PORT
      LAYER met3 ;
        RECT 0.000 408.040 4.000 408.640 ;
    END
  END result[81]
  PIN result[82]
    DIRECTION OUTPUT ;
    USE SIGNAL ;
    ANTENNADIFFAREA 0.340600 ;
    PORT
      LAYER met3 ;
        RECT 0.000 412.120 4.000 412.720 ;
    END
  END result[82]
  PIN result[83]
    DIRECTION OUTPUT ;
    USE SIGNAL ;
    ANTENNADIFFAREA 0.340600 ;
    PORT
      LAYER met3 ;
        RECT 0.000 416.200 4.000 416.800 ;
    END
  END result[83]
  PIN result[84]
    DIRECTION OUTPUT ;
    USE SIGNAL ;
    ANTENNADIFFAREA 0.340600 ;
    PORT
      LAYER met3 ;
        RECT 0.000 420.280 4.000 420.880 ;
    END
  END result[84]
  PIN result[85]
    DIRECTION OUTPUT ;
    USE SIGNAL ;
    ANTENNADIFFAREA 0.340600 ;
    PORT
      LAYER met3 ;
        RECT 0.000 424.360 4.000 424.960 ;
    END
  END result[85]
  PIN result[86]
    DIRECTION OUTPUT ;
    USE SIGNAL ;
    ANTENNADIFFAREA 0.340600 ;
    PORT
      LAYER met3 ;
        RECT 0.000 428.440 4.000 429.040 ;
    END
  END result[86]
  PIN result[87]
    DIRECTION OUTPUT ;
    USE SIGNAL ;
    ANTENNADIFFAREA 0.340600 ;
    PORT
      LAYER met3 ;
        RECT 0.000 432.520 4.000 433.120 ;
    END
  END result[87]
  PIN result[88]
    DIRECTION OUTPUT ;
    USE SIGNAL ;
    ANTENNADIFFAREA 0.340600 ;
    PORT
      LAYER met3 ;
        RECT 0.000 436.600 4.000 437.200 ;
    END
  END result[88]
  PIN result[89]
    DIRECTION OUTPUT ;
    USE SIGNAL ;
    ANTENNADIFFAREA 0.340600 ;
    PORT
      LAYER met3 ;
        RECT 0.000 440.680 4.000 441.280 ;
    END
  END result[89]
  PIN result[8]
    DIRECTION OUTPUT ;
    USE SIGNAL ;
    ANTENNADIFFAREA 0.340600 ;
    PORT
      LAYER met3 ;
        RECT 0.000 110.200 4.000 110.800 ;
    END
  END result[8]
  PIN result[90]
    DIRECTION OUTPUT ;
    USE SIGNAL ;
    ANTENNADIFFAREA 0.340600 ;
    PORT
      LAYER met3 ;
        RECT 0.000 444.760 4.000 445.360 ;
    END
  END result[90]
  PIN result[91]
    DIRECTION OUTPUT ;
    USE SIGNAL ;
    ANTENNADIFFAREA 0.340600 ;
    PORT
      LAYER met3 ;
        RECT 0.000 448.840 4.000 449.440 ;
    END
  END result[91]
  PIN result[92]
    DIRECTION OUTPUT ;
    USE SIGNAL ;
    ANTENNADIFFAREA 0.340600 ;
    PORT
      LAYER met3 ;
        RECT 0.000 452.920 4.000 453.520 ;
    END
  END result[92]
  PIN result[93]
    DIRECTION OUTPUT ;
    USE SIGNAL ;
    ANTENNADIFFAREA 0.340600 ;
    PORT
      LAYER met3 ;
        RECT 0.000 457.000 4.000 457.600 ;
    END
  END result[93]
  PIN result[94]
    DIRECTION OUTPUT ;
    USE SIGNAL ;
    ANTENNADIFFAREA 0.340600 ;
    PORT
      LAYER met3 ;
        RECT 0.000 461.080 4.000 461.680 ;
    END
  END result[94]
  PIN result[95]
    DIRECTION OUTPUT ;
    USE SIGNAL ;
    ANTENNADIFFAREA 0.340600 ;
    PORT
      LAYER met3 ;
        RECT 0.000 465.160 4.000 465.760 ;
    END
  END result[95]
  PIN result[96]
    DIRECTION OUTPUT ;
    USE SIGNAL ;
    ANTENNADIFFAREA 0.340600 ;
    PORT
      LAYER met3 ;
        RECT 0.000 469.240 4.000 469.840 ;
    END
  END result[96]
  PIN result[97]
    DIRECTION OUTPUT ;
    USE SIGNAL ;
    ANTENNADIFFAREA 0.340600 ;
    PORT
      LAYER met3 ;
        RECT 0.000 473.320 4.000 473.920 ;
    END
  END result[97]
  PIN result[98]
    DIRECTION OUTPUT ;
    USE SIGNAL ;
    ANTENNADIFFAREA 0.340600 ;
    PORT
      LAYER met3 ;
        RECT 0.000 477.400 4.000 478.000 ;
    END
  END result[98]
  PIN result[99]
    DIRECTION OUTPUT ;
    USE SIGNAL ;
    ANTENNADIFFAREA 0.340600 ;
    PORT
      LAYER met3 ;
        RECT 0.000 481.480 4.000 482.080 ;
    END
  END result[99]
  PIN result[9]
    DIRECTION OUTPUT ;
    USE SIGNAL ;
    ANTENNADIFFAREA 0.340600 ;
    PORT
      LAYER met3 ;
        RECT 0.000 114.280 4.000 114.880 ;
    END
  END result[9]
  PIN result_valid
    DIRECTION OUTPUT ;
    USE SIGNAL ;
    ANTENNADIFFAREA 0.340600 ;
    PORT
      LAYER met2 ;
        RECT 621.550 671.155 621.830 675.155 ;
    END
  END result_valid
  OBS
      LAYER nwell ;
        RECT 5.330 10.795 658.910 663.765 ;
      LAYER li1 ;
        RECT 5.520 10.795 658.720 663.765 ;
      LAYER met1 ;
        RECT 2.830 2.760 658.720 663.920 ;
      LAYER met2 ;
        RECT 2.850 670.875 41.670 671.685 ;
        RECT 42.510 670.875 124.470 671.685 ;
        RECT 125.310 670.875 207.270 671.685 ;
        RECT 208.110 670.875 290.070 671.685 ;
        RECT 290.910 670.875 372.870 671.685 ;
        RECT 373.710 670.875 455.670 671.685 ;
        RECT 456.510 670.875 538.470 671.685 ;
        RECT 539.310 670.875 621.270 671.685 ;
        RECT 622.110 670.875 658.170 671.685 ;
        RECT 2.850 4.280 658.170 670.875 ;
        RECT 2.850 1.515 38.450 4.280 ;
        RECT 39.290 1.515 40.750 4.280 ;
        RECT 41.590 1.515 43.050 4.280 ;
        RECT 43.890 1.515 45.350 4.280 ;
        RECT 46.190 1.515 47.650 4.280 ;
        RECT 48.490 1.515 49.950 4.280 ;
        RECT 50.790 1.515 52.250 4.280 ;
        RECT 53.090 1.515 54.550 4.280 ;
        RECT 55.390 1.515 56.850 4.280 ;
        RECT 57.690 1.515 59.150 4.280 ;
        RECT 59.990 1.515 61.450 4.280 ;
        RECT 62.290 1.515 63.750 4.280 ;
        RECT 64.590 1.515 66.050 4.280 ;
        RECT 66.890 1.515 68.350 4.280 ;
        RECT 69.190 1.515 70.650 4.280 ;
        RECT 71.490 1.515 72.950 4.280 ;
        RECT 73.790 1.515 75.250 4.280 ;
        RECT 76.090 1.515 77.550 4.280 ;
        RECT 78.390 1.515 79.850 4.280 ;
        RECT 80.690 1.515 82.150 4.280 ;
        RECT 82.990 1.515 84.450 4.280 ;
        RECT 85.290 1.515 86.750 4.280 ;
        RECT 87.590 1.515 89.050 4.280 ;
        RECT 89.890 1.515 91.350 4.280 ;
        RECT 92.190 1.515 93.650 4.280 ;
        RECT 94.490 1.515 95.950 4.280 ;
        RECT 96.790 1.515 98.250 4.280 ;
        RECT 99.090 1.515 100.550 4.280 ;
        RECT 101.390 1.515 102.850 4.280 ;
        RECT 103.690 1.515 105.150 4.280 ;
        RECT 105.990 1.515 107.450 4.280 ;
        RECT 108.290 1.515 109.750 4.280 ;
        RECT 110.590 1.515 112.050 4.280 ;
        RECT 112.890 1.515 114.350 4.280 ;
        RECT 115.190 1.515 116.650 4.280 ;
        RECT 117.490 1.515 118.950 4.280 ;
        RECT 119.790 1.515 121.250 4.280 ;
        RECT 122.090 1.515 123.550 4.280 ;
        RECT 124.390 1.515 125.850 4.280 ;
        RECT 126.690 1.515 128.150 4.280 ;
        RECT 128.990 1.515 130.450 4.280 ;
        RECT 131.290 1.515 132.750 4.280 ;
        RECT 133.590 1.515 135.050 4.280 ;
        RECT 135.890 1.515 137.350 4.280 ;
        RECT 138.190 1.515 139.650 4.280 ;
        RECT 140.490 1.515 141.950 4.280 ;
        RECT 142.790 1.515 144.250 4.280 ;
        RECT 145.090 1.515 146.550 4.280 ;
        RECT 147.390 1.515 148.850 4.280 ;
        RECT 149.690 1.515 151.150 4.280 ;
        RECT 151.990 1.515 153.450 4.280 ;
        RECT 154.290 1.515 155.750 4.280 ;
        RECT 156.590 1.515 158.050 4.280 ;
        RECT 158.890 1.515 160.350 4.280 ;
        RECT 161.190 1.515 162.650 4.280 ;
        RECT 163.490 1.515 164.950 4.280 ;
        RECT 165.790 1.515 167.250 4.280 ;
        RECT 168.090 1.515 169.550 4.280 ;
        RECT 170.390 1.515 171.850 4.280 ;
        RECT 172.690 1.515 174.150 4.280 ;
        RECT 174.990 1.515 176.450 4.280 ;
        RECT 177.290 1.515 178.750 4.280 ;
        RECT 179.590 1.515 181.050 4.280 ;
        RECT 181.890 1.515 183.350 4.280 ;
        RECT 184.190 1.515 185.650 4.280 ;
        RECT 186.490 1.515 187.950 4.280 ;
        RECT 188.790 1.515 190.250 4.280 ;
        RECT 191.090 1.515 192.550 4.280 ;
        RECT 193.390 1.515 194.850 4.280 ;
        RECT 195.690 1.515 197.150 4.280 ;
        RECT 197.990 1.515 199.450 4.280 ;
        RECT 200.290 1.515 201.750 4.280 ;
        RECT 202.590 1.515 204.050 4.280 ;
        RECT 204.890 1.515 206.350 4.280 ;
        RECT 207.190 1.515 208.650 4.280 ;
        RECT 209.490 1.515 210.950 4.280 ;
        RECT 211.790 1.515 213.250 4.280 ;
        RECT 214.090 1.515 215.550 4.280 ;
        RECT 216.390 1.515 217.850 4.280 ;
        RECT 218.690 1.515 220.150 4.280 ;
        RECT 220.990 1.515 222.450 4.280 ;
        RECT 223.290 1.515 224.750 4.280 ;
        RECT 225.590 1.515 227.050 4.280 ;
        RECT 227.890 1.515 229.350 4.280 ;
        RECT 230.190 1.515 231.650 4.280 ;
        RECT 232.490 1.515 233.950 4.280 ;
        RECT 234.790 1.515 236.250 4.280 ;
        RECT 237.090 1.515 238.550 4.280 ;
        RECT 239.390 1.515 240.850 4.280 ;
        RECT 241.690 1.515 243.150 4.280 ;
        RECT 243.990 1.515 245.450 4.280 ;
        RECT 246.290 1.515 247.750 4.280 ;
        RECT 248.590 1.515 250.050 4.280 ;
        RECT 250.890 1.515 252.350 4.280 ;
        RECT 253.190 1.515 254.650 4.280 ;
        RECT 255.490 1.515 256.950 4.280 ;
        RECT 257.790 1.515 259.250 4.280 ;
        RECT 260.090 1.515 261.550 4.280 ;
        RECT 262.390 1.515 263.850 4.280 ;
        RECT 264.690 1.515 266.150 4.280 ;
        RECT 266.990 1.515 268.450 4.280 ;
        RECT 269.290 1.515 270.750 4.280 ;
        RECT 271.590 1.515 273.050 4.280 ;
        RECT 273.890 1.515 275.350 4.280 ;
        RECT 276.190 1.515 277.650 4.280 ;
        RECT 278.490 1.515 279.950 4.280 ;
        RECT 280.790 1.515 282.250 4.280 ;
        RECT 283.090 1.515 284.550 4.280 ;
        RECT 285.390 1.515 286.850 4.280 ;
        RECT 287.690 1.515 289.150 4.280 ;
        RECT 289.990 1.515 291.450 4.280 ;
        RECT 292.290 1.515 293.750 4.280 ;
        RECT 294.590 1.515 296.050 4.280 ;
        RECT 296.890 1.515 298.350 4.280 ;
        RECT 299.190 1.515 300.650 4.280 ;
        RECT 301.490 1.515 302.950 4.280 ;
        RECT 303.790 1.515 305.250 4.280 ;
        RECT 306.090 1.515 307.550 4.280 ;
        RECT 308.390 1.515 309.850 4.280 ;
        RECT 310.690 1.515 312.150 4.280 ;
        RECT 312.990 1.515 314.450 4.280 ;
        RECT 315.290 1.515 316.750 4.280 ;
        RECT 317.590 1.515 319.050 4.280 ;
        RECT 319.890 1.515 321.350 4.280 ;
        RECT 322.190 1.515 323.650 4.280 ;
        RECT 324.490 1.515 325.950 4.280 ;
        RECT 326.790 1.515 328.250 4.280 ;
        RECT 329.090 1.515 330.550 4.280 ;
        RECT 331.390 1.515 332.850 4.280 ;
        RECT 333.690 1.515 335.150 4.280 ;
        RECT 335.990 1.515 337.450 4.280 ;
        RECT 338.290 1.515 339.750 4.280 ;
        RECT 340.590 1.515 342.050 4.280 ;
        RECT 342.890 1.515 344.350 4.280 ;
        RECT 345.190 1.515 346.650 4.280 ;
        RECT 347.490 1.515 348.950 4.280 ;
        RECT 349.790 1.515 351.250 4.280 ;
        RECT 352.090 1.515 353.550 4.280 ;
        RECT 354.390 1.515 355.850 4.280 ;
        RECT 356.690 1.515 358.150 4.280 ;
        RECT 358.990 1.515 360.450 4.280 ;
        RECT 361.290 1.515 362.750 4.280 ;
        RECT 363.590 1.515 365.050 4.280 ;
        RECT 365.890 1.515 367.350 4.280 ;
        RECT 368.190 1.515 369.650 4.280 ;
        RECT 370.490 1.515 371.950 4.280 ;
        RECT 372.790 1.515 374.250 4.280 ;
        RECT 375.090 1.515 376.550 4.280 ;
        RECT 377.390 1.515 378.850 4.280 ;
        RECT 379.690 1.515 381.150 4.280 ;
        RECT 381.990 1.515 383.450 4.280 ;
        RECT 384.290 1.515 385.750 4.280 ;
        RECT 386.590 1.515 388.050 4.280 ;
        RECT 388.890 1.515 390.350 4.280 ;
        RECT 391.190 1.515 392.650 4.280 ;
        RECT 393.490 1.515 394.950 4.280 ;
        RECT 395.790 1.515 397.250 4.280 ;
        RECT 398.090 1.515 399.550 4.280 ;
        RECT 400.390 1.515 401.850 4.280 ;
        RECT 402.690 1.515 404.150 4.280 ;
        RECT 404.990 1.515 406.450 4.280 ;
        RECT 407.290 1.515 408.750 4.280 ;
        RECT 409.590 1.515 411.050 4.280 ;
        RECT 411.890 1.515 413.350 4.280 ;
        RECT 414.190 1.515 415.650 4.280 ;
        RECT 416.490 1.515 417.950 4.280 ;
        RECT 418.790 1.515 420.250 4.280 ;
        RECT 421.090 1.515 422.550 4.280 ;
        RECT 423.390 1.515 424.850 4.280 ;
        RECT 425.690 1.515 427.150 4.280 ;
        RECT 427.990 1.515 429.450 4.280 ;
        RECT 430.290 1.515 431.750 4.280 ;
        RECT 432.590 1.515 434.050 4.280 ;
        RECT 434.890 1.515 436.350 4.280 ;
        RECT 437.190 1.515 438.650 4.280 ;
        RECT 439.490 1.515 440.950 4.280 ;
        RECT 441.790 1.515 443.250 4.280 ;
        RECT 444.090 1.515 445.550 4.280 ;
        RECT 446.390 1.515 447.850 4.280 ;
        RECT 448.690 1.515 450.150 4.280 ;
        RECT 450.990 1.515 452.450 4.280 ;
        RECT 453.290 1.515 454.750 4.280 ;
        RECT 455.590 1.515 457.050 4.280 ;
        RECT 457.890 1.515 459.350 4.280 ;
        RECT 460.190 1.515 461.650 4.280 ;
        RECT 462.490 1.515 463.950 4.280 ;
        RECT 464.790 1.515 466.250 4.280 ;
        RECT 467.090 1.515 468.550 4.280 ;
        RECT 469.390 1.515 470.850 4.280 ;
        RECT 471.690 1.515 473.150 4.280 ;
        RECT 473.990 1.515 475.450 4.280 ;
        RECT 476.290 1.515 477.750 4.280 ;
        RECT 478.590 1.515 480.050 4.280 ;
        RECT 480.890 1.515 482.350 4.280 ;
        RECT 483.190 1.515 484.650 4.280 ;
        RECT 485.490 1.515 486.950 4.280 ;
        RECT 487.790 1.515 489.250 4.280 ;
        RECT 490.090 1.515 491.550 4.280 ;
        RECT 492.390 1.515 493.850 4.280 ;
        RECT 494.690 1.515 496.150 4.280 ;
        RECT 496.990 1.515 498.450 4.280 ;
        RECT 499.290 1.515 500.750 4.280 ;
        RECT 501.590 1.515 503.050 4.280 ;
        RECT 503.890 1.515 505.350 4.280 ;
        RECT 506.190 1.515 507.650 4.280 ;
        RECT 508.490 1.515 509.950 4.280 ;
        RECT 510.790 1.515 512.250 4.280 ;
        RECT 513.090 1.515 514.550 4.280 ;
        RECT 515.390 1.515 516.850 4.280 ;
        RECT 517.690 1.515 519.150 4.280 ;
        RECT 519.990 1.515 521.450 4.280 ;
        RECT 522.290 1.515 523.750 4.280 ;
        RECT 524.590 1.515 526.050 4.280 ;
        RECT 526.890 1.515 528.350 4.280 ;
        RECT 529.190 1.515 530.650 4.280 ;
        RECT 531.490 1.515 532.950 4.280 ;
        RECT 533.790 1.515 535.250 4.280 ;
        RECT 536.090 1.515 537.550 4.280 ;
        RECT 538.390 1.515 539.850 4.280 ;
        RECT 540.690 1.515 542.150 4.280 ;
        RECT 542.990 1.515 544.450 4.280 ;
        RECT 545.290 1.515 546.750 4.280 ;
        RECT 547.590 1.515 549.050 4.280 ;
        RECT 549.890 1.515 551.350 4.280 ;
        RECT 552.190 1.515 553.650 4.280 ;
        RECT 554.490 1.515 555.950 4.280 ;
        RECT 556.790 1.515 558.250 4.280 ;
        RECT 559.090 1.515 560.550 4.280 ;
        RECT 561.390 1.515 562.850 4.280 ;
        RECT 563.690 1.515 565.150 4.280 ;
        RECT 565.990 1.515 567.450 4.280 ;
        RECT 568.290 1.515 569.750 4.280 ;
        RECT 570.590 1.515 572.050 4.280 ;
        RECT 572.890 1.515 574.350 4.280 ;
        RECT 575.190 1.515 576.650 4.280 ;
        RECT 577.490 1.515 578.950 4.280 ;
        RECT 579.790 1.515 581.250 4.280 ;
        RECT 582.090 1.515 583.550 4.280 ;
        RECT 584.390 1.515 585.850 4.280 ;
        RECT 586.690 1.515 588.150 4.280 ;
        RECT 588.990 1.515 590.450 4.280 ;
        RECT 591.290 1.515 592.750 4.280 ;
        RECT 593.590 1.515 595.050 4.280 ;
        RECT 595.890 1.515 597.350 4.280 ;
        RECT 598.190 1.515 599.650 4.280 ;
        RECT 600.490 1.515 601.950 4.280 ;
        RECT 602.790 1.515 604.250 4.280 ;
        RECT 605.090 1.515 606.550 4.280 ;
        RECT 607.390 1.515 608.850 4.280 ;
        RECT 609.690 1.515 611.150 4.280 ;
        RECT 611.990 1.515 613.450 4.280 ;
        RECT 614.290 1.515 615.750 4.280 ;
        RECT 616.590 1.515 618.050 4.280 ;
        RECT 618.890 1.515 620.350 4.280 ;
        RECT 621.190 1.515 622.650 4.280 ;
        RECT 623.490 1.515 624.950 4.280 ;
        RECT 625.790 1.515 658.170 4.280 ;
      LAYER met3 ;
        RECT 2.825 596.720 660.435 671.665 ;
        RECT 4.400 595.320 660.035 596.720 ;
        RECT 2.825 592.640 660.435 595.320 ;
        RECT 4.400 591.240 660.035 592.640 ;
        RECT 2.825 588.560 660.435 591.240 ;
        RECT 4.400 587.160 660.035 588.560 ;
        RECT 2.825 584.480 660.435 587.160 ;
        RECT 4.400 583.080 660.035 584.480 ;
        RECT 2.825 580.400 660.435 583.080 ;
        RECT 4.400 579.000 660.035 580.400 ;
        RECT 2.825 576.320 660.435 579.000 ;
        RECT 4.400 574.920 660.035 576.320 ;
        RECT 2.825 572.240 660.435 574.920 ;
        RECT 4.400 570.840 660.035 572.240 ;
        RECT 2.825 568.160 660.435 570.840 ;
        RECT 4.400 566.760 660.035 568.160 ;
        RECT 2.825 564.080 660.435 566.760 ;
        RECT 4.400 562.680 660.035 564.080 ;
        RECT 2.825 560.000 660.435 562.680 ;
        RECT 4.400 558.600 660.035 560.000 ;
        RECT 2.825 555.920 660.435 558.600 ;
        RECT 4.400 554.520 660.035 555.920 ;
        RECT 2.825 551.840 660.435 554.520 ;
        RECT 4.400 550.440 660.035 551.840 ;
        RECT 2.825 547.760 660.435 550.440 ;
        RECT 4.400 546.360 660.035 547.760 ;
        RECT 2.825 543.680 660.435 546.360 ;
        RECT 4.400 542.280 660.035 543.680 ;
        RECT 2.825 539.600 660.435 542.280 ;
        RECT 4.400 538.200 660.035 539.600 ;
        RECT 2.825 535.520 660.435 538.200 ;
        RECT 4.400 534.120 660.035 535.520 ;
        RECT 2.825 531.440 660.435 534.120 ;
        RECT 4.400 530.040 660.035 531.440 ;
        RECT 2.825 527.360 660.435 530.040 ;
        RECT 4.400 525.960 660.035 527.360 ;
        RECT 2.825 523.280 660.435 525.960 ;
        RECT 4.400 521.880 660.035 523.280 ;
        RECT 2.825 519.200 660.435 521.880 ;
        RECT 4.400 517.800 660.035 519.200 ;
        RECT 2.825 515.120 660.435 517.800 ;
        RECT 4.400 513.720 660.035 515.120 ;
        RECT 2.825 511.040 660.435 513.720 ;
        RECT 4.400 509.640 660.035 511.040 ;
        RECT 2.825 506.960 660.435 509.640 ;
        RECT 4.400 505.560 660.035 506.960 ;
        RECT 2.825 502.880 660.435 505.560 ;
        RECT 4.400 501.480 660.035 502.880 ;
        RECT 2.825 498.800 660.435 501.480 ;
        RECT 4.400 497.400 660.035 498.800 ;
        RECT 2.825 494.720 660.435 497.400 ;
        RECT 4.400 493.320 660.035 494.720 ;
        RECT 2.825 490.640 660.435 493.320 ;
        RECT 4.400 489.240 660.035 490.640 ;
        RECT 2.825 486.560 660.435 489.240 ;
        RECT 4.400 485.160 660.035 486.560 ;
        RECT 2.825 482.480 660.435 485.160 ;
        RECT 4.400 481.080 660.035 482.480 ;
        RECT 2.825 478.400 660.435 481.080 ;
        RECT 4.400 477.000 660.035 478.400 ;
        RECT 2.825 474.320 660.435 477.000 ;
        RECT 4.400 472.920 660.035 474.320 ;
        RECT 2.825 470.240 660.435 472.920 ;
        RECT 4.400 468.840 660.035 470.240 ;
        RECT 2.825 466.160 660.435 468.840 ;
        RECT 4.400 464.760 660.035 466.160 ;
        RECT 2.825 462.080 660.435 464.760 ;
        RECT 4.400 460.680 660.035 462.080 ;
        RECT 2.825 458.000 660.435 460.680 ;
        RECT 4.400 456.600 660.035 458.000 ;
        RECT 2.825 453.920 660.435 456.600 ;
        RECT 4.400 452.520 660.035 453.920 ;
        RECT 2.825 449.840 660.435 452.520 ;
        RECT 4.400 448.440 660.035 449.840 ;
        RECT 2.825 445.760 660.435 448.440 ;
        RECT 4.400 444.360 660.035 445.760 ;
        RECT 2.825 441.680 660.435 444.360 ;
        RECT 4.400 440.280 660.035 441.680 ;
        RECT 2.825 437.600 660.435 440.280 ;
        RECT 4.400 436.200 660.035 437.600 ;
        RECT 2.825 433.520 660.435 436.200 ;
        RECT 4.400 432.120 660.035 433.520 ;
        RECT 2.825 429.440 660.435 432.120 ;
        RECT 4.400 428.040 660.035 429.440 ;
        RECT 2.825 425.360 660.435 428.040 ;
        RECT 4.400 423.960 660.035 425.360 ;
        RECT 2.825 421.280 660.435 423.960 ;
        RECT 4.400 419.880 660.035 421.280 ;
        RECT 2.825 417.200 660.435 419.880 ;
        RECT 4.400 415.800 660.035 417.200 ;
        RECT 2.825 413.120 660.435 415.800 ;
        RECT 4.400 411.720 660.035 413.120 ;
        RECT 2.825 409.040 660.435 411.720 ;
        RECT 4.400 407.640 660.035 409.040 ;
        RECT 2.825 404.960 660.435 407.640 ;
        RECT 4.400 403.560 660.035 404.960 ;
        RECT 2.825 400.880 660.435 403.560 ;
        RECT 4.400 399.480 660.035 400.880 ;
        RECT 2.825 396.800 660.435 399.480 ;
        RECT 4.400 395.400 660.035 396.800 ;
        RECT 2.825 392.720 660.435 395.400 ;
        RECT 4.400 391.320 660.035 392.720 ;
        RECT 2.825 388.640 660.435 391.320 ;
        RECT 4.400 387.240 660.035 388.640 ;
        RECT 2.825 384.560 660.435 387.240 ;
        RECT 4.400 383.160 660.035 384.560 ;
        RECT 2.825 380.480 660.435 383.160 ;
        RECT 4.400 379.080 660.035 380.480 ;
        RECT 2.825 376.400 660.435 379.080 ;
        RECT 4.400 375.000 660.035 376.400 ;
        RECT 2.825 372.320 660.435 375.000 ;
        RECT 4.400 370.920 660.035 372.320 ;
        RECT 2.825 368.240 660.435 370.920 ;
        RECT 4.400 366.840 660.035 368.240 ;
        RECT 2.825 364.160 660.435 366.840 ;
        RECT 4.400 362.760 660.035 364.160 ;
        RECT 2.825 360.080 660.435 362.760 ;
        RECT 4.400 358.680 660.035 360.080 ;
        RECT 2.825 356.000 660.435 358.680 ;
        RECT 4.400 354.600 660.035 356.000 ;
        RECT 2.825 351.920 660.435 354.600 ;
        RECT 4.400 350.520 660.035 351.920 ;
        RECT 2.825 347.840 660.435 350.520 ;
        RECT 4.400 346.440 660.035 347.840 ;
        RECT 2.825 343.760 660.435 346.440 ;
        RECT 4.400 342.360 660.035 343.760 ;
        RECT 2.825 339.680 660.435 342.360 ;
        RECT 4.400 338.280 660.035 339.680 ;
        RECT 2.825 335.600 660.435 338.280 ;
        RECT 4.400 334.200 660.035 335.600 ;
        RECT 2.825 331.520 660.435 334.200 ;
        RECT 4.400 330.120 660.035 331.520 ;
        RECT 2.825 327.440 660.435 330.120 ;
        RECT 4.400 326.040 660.035 327.440 ;
        RECT 2.825 323.360 660.435 326.040 ;
        RECT 4.400 321.960 660.035 323.360 ;
        RECT 2.825 319.280 660.435 321.960 ;
        RECT 4.400 317.880 660.035 319.280 ;
        RECT 2.825 315.200 660.435 317.880 ;
        RECT 4.400 313.800 660.035 315.200 ;
        RECT 2.825 311.120 660.435 313.800 ;
        RECT 4.400 309.720 660.035 311.120 ;
        RECT 2.825 307.040 660.435 309.720 ;
        RECT 4.400 305.640 660.035 307.040 ;
        RECT 2.825 302.960 660.435 305.640 ;
        RECT 4.400 301.560 660.035 302.960 ;
        RECT 2.825 298.880 660.435 301.560 ;
        RECT 4.400 297.480 660.035 298.880 ;
        RECT 2.825 294.800 660.435 297.480 ;
        RECT 4.400 293.400 660.035 294.800 ;
        RECT 2.825 290.720 660.435 293.400 ;
        RECT 4.400 289.320 660.035 290.720 ;
        RECT 2.825 286.640 660.435 289.320 ;
        RECT 4.400 285.240 660.035 286.640 ;
        RECT 2.825 282.560 660.435 285.240 ;
        RECT 4.400 281.160 660.035 282.560 ;
        RECT 2.825 278.480 660.435 281.160 ;
        RECT 4.400 277.080 660.035 278.480 ;
        RECT 2.825 274.400 660.435 277.080 ;
        RECT 4.400 273.000 660.035 274.400 ;
        RECT 2.825 270.320 660.435 273.000 ;
        RECT 4.400 268.920 660.035 270.320 ;
        RECT 2.825 266.240 660.435 268.920 ;
        RECT 4.400 264.840 660.035 266.240 ;
        RECT 2.825 262.160 660.435 264.840 ;
        RECT 4.400 260.760 660.035 262.160 ;
        RECT 2.825 258.080 660.435 260.760 ;
        RECT 4.400 256.680 660.035 258.080 ;
        RECT 2.825 254.000 660.435 256.680 ;
        RECT 4.400 252.600 660.035 254.000 ;
        RECT 2.825 249.920 660.435 252.600 ;
        RECT 4.400 248.520 660.035 249.920 ;
        RECT 2.825 245.840 660.435 248.520 ;
        RECT 4.400 244.440 660.035 245.840 ;
        RECT 2.825 241.760 660.435 244.440 ;
        RECT 4.400 240.360 660.035 241.760 ;
        RECT 2.825 237.680 660.435 240.360 ;
        RECT 4.400 236.280 660.035 237.680 ;
        RECT 2.825 233.600 660.435 236.280 ;
        RECT 4.400 232.200 660.035 233.600 ;
        RECT 2.825 229.520 660.435 232.200 ;
        RECT 4.400 228.120 660.035 229.520 ;
        RECT 2.825 225.440 660.435 228.120 ;
        RECT 4.400 224.040 660.035 225.440 ;
        RECT 2.825 221.360 660.435 224.040 ;
        RECT 4.400 219.960 660.035 221.360 ;
        RECT 2.825 217.280 660.435 219.960 ;
        RECT 4.400 215.880 660.035 217.280 ;
        RECT 2.825 213.200 660.435 215.880 ;
        RECT 4.400 211.800 660.035 213.200 ;
        RECT 2.825 209.120 660.435 211.800 ;
        RECT 4.400 207.720 660.035 209.120 ;
        RECT 2.825 205.040 660.435 207.720 ;
        RECT 4.400 203.640 660.035 205.040 ;
        RECT 2.825 200.960 660.435 203.640 ;
        RECT 4.400 199.560 660.035 200.960 ;
        RECT 2.825 196.880 660.435 199.560 ;
        RECT 4.400 195.480 660.035 196.880 ;
        RECT 2.825 192.800 660.435 195.480 ;
        RECT 4.400 191.400 660.035 192.800 ;
        RECT 2.825 188.720 660.435 191.400 ;
        RECT 4.400 187.320 660.035 188.720 ;
        RECT 2.825 184.640 660.435 187.320 ;
        RECT 4.400 183.240 660.035 184.640 ;
        RECT 2.825 180.560 660.435 183.240 ;
        RECT 4.400 179.160 660.035 180.560 ;
        RECT 2.825 176.480 660.435 179.160 ;
        RECT 4.400 175.080 660.035 176.480 ;
        RECT 2.825 172.400 660.435 175.080 ;
        RECT 4.400 171.000 660.035 172.400 ;
        RECT 2.825 168.320 660.435 171.000 ;
        RECT 4.400 166.920 660.035 168.320 ;
        RECT 2.825 164.240 660.435 166.920 ;
        RECT 4.400 162.840 660.035 164.240 ;
        RECT 2.825 160.160 660.435 162.840 ;
        RECT 4.400 158.760 660.035 160.160 ;
        RECT 2.825 156.080 660.435 158.760 ;
        RECT 4.400 154.680 660.035 156.080 ;
        RECT 2.825 152.000 660.435 154.680 ;
        RECT 4.400 150.600 660.035 152.000 ;
        RECT 2.825 147.920 660.435 150.600 ;
        RECT 4.400 146.520 660.035 147.920 ;
        RECT 2.825 143.840 660.435 146.520 ;
        RECT 4.400 142.440 660.035 143.840 ;
        RECT 2.825 139.760 660.435 142.440 ;
        RECT 4.400 138.360 660.035 139.760 ;
        RECT 2.825 135.680 660.435 138.360 ;
        RECT 4.400 134.280 660.035 135.680 ;
        RECT 2.825 131.600 660.435 134.280 ;
        RECT 4.400 130.200 660.035 131.600 ;
        RECT 2.825 127.520 660.435 130.200 ;
        RECT 4.400 126.120 660.035 127.520 ;
        RECT 2.825 123.440 660.435 126.120 ;
        RECT 4.400 122.040 660.035 123.440 ;
        RECT 2.825 119.360 660.435 122.040 ;
        RECT 4.400 117.960 660.035 119.360 ;
        RECT 2.825 115.280 660.435 117.960 ;
        RECT 4.400 113.880 660.035 115.280 ;
        RECT 2.825 111.200 660.435 113.880 ;
        RECT 4.400 109.800 660.035 111.200 ;
        RECT 2.825 107.120 660.435 109.800 ;
        RECT 4.400 105.720 660.035 107.120 ;
        RECT 2.825 103.040 660.435 105.720 ;
        RECT 4.400 101.640 660.035 103.040 ;
        RECT 2.825 98.960 660.435 101.640 ;
        RECT 4.400 97.560 660.035 98.960 ;
        RECT 2.825 94.880 660.435 97.560 ;
        RECT 4.400 93.480 660.035 94.880 ;
        RECT 2.825 90.800 660.435 93.480 ;
        RECT 4.400 89.400 660.035 90.800 ;
        RECT 2.825 86.720 660.435 89.400 ;
        RECT 4.400 85.320 660.035 86.720 ;
        RECT 2.825 82.640 660.435 85.320 ;
        RECT 4.400 81.240 660.035 82.640 ;
        RECT 2.825 78.560 660.435 81.240 ;
        RECT 4.400 77.160 660.035 78.560 ;
        RECT 2.825 1.535 660.435 77.160 ;
      LAYER met4 ;
        RECT 3.070 664.320 656.090 671.665 ;
        RECT 3.070 10.240 9.120 664.320 ;
        RECT 11.920 10.240 12.820 664.320 ;
        RECT 15.620 10.240 39.120 664.320 ;
        RECT 41.920 10.240 42.820 664.320 ;
        RECT 45.620 10.240 69.120 664.320 ;
        RECT 71.920 10.240 72.820 664.320 ;
        RECT 75.620 10.240 99.120 664.320 ;
        RECT 101.920 10.240 102.820 664.320 ;
        RECT 105.620 10.240 129.120 664.320 ;
        RECT 131.920 10.240 132.820 664.320 ;
        RECT 135.620 10.240 159.120 664.320 ;
        RECT 161.920 10.240 162.820 664.320 ;
        RECT 165.620 10.240 189.120 664.320 ;
        RECT 191.920 10.240 192.820 664.320 ;
        RECT 195.620 10.240 219.120 664.320 ;
        RECT 221.920 10.240 222.820 664.320 ;
        RECT 225.620 10.240 249.120 664.320 ;
        RECT 251.920 10.240 252.820 664.320 ;
        RECT 255.620 10.240 279.120 664.320 ;
        RECT 281.920 10.240 282.820 664.320 ;
        RECT 285.620 10.240 309.120 664.320 ;
        RECT 311.920 10.240 312.820 664.320 ;
        RECT 315.620 10.240 339.120 664.320 ;
        RECT 341.920 10.240 342.820 664.320 ;
        RECT 345.620 10.240 369.120 664.320 ;
        RECT 371.920 10.240 372.820 664.320 ;
        RECT 375.620 10.240 399.120 664.320 ;
        RECT 401.920 10.240 402.820 664.320 ;
        RECT 405.620 10.240 429.120 664.320 ;
        RECT 431.920 10.240 432.820 664.320 ;
        RECT 435.620 10.240 459.120 664.320 ;
        RECT 461.920 10.240 462.820 664.320 ;
        RECT 465.620 10.240 489.120 664.320 ;
        RECT 491.920 10.240 492.820 664.320 ;
        RECT 495.620 10.240 519.120 664.320 ;
        RECT 521.920 10.240 522.820 664.320 ;
        RECT 525.620 10.240 549.120 664.320 ;
        RECT 551.920 10.240 552.820 664.320 ;
        RECT 555.620 10.240 579.120 664.320 ;
        RECT 581.920 10.240 582.820 664.320 ;
        RECT 585.620 10.240 609.120 664.320 ;
        RECT 611.920 10.240 612.820 664.320 ;
        RECT 615.620 10.240 639.120 664.320 ;
        RECT 641.920 10.240 642.820 664.320 ;
        RECT 645.620 10.240 656.090 664.320 ;
        RECT 3.070 1.535 656.090 10.240 ;
      LAYER met5 ;
        RECT 7.020 562.180 656.300 570.300 ;
        RECT 7.020 532.180 656.300 553.280 ;
        RECT 7.020 502.180 656.300 523.280 ;
        RECT 7.020 472.180 656.300 493.280 ;
        RECT 7.020 442.180 656.300 463.280 ;
        RECT 7.020 412.180 656.300 433.280 ;
        RECT 7.020 382.180 656.300 403.280 ;
        RECT 7.020 352.180 656.300 373.280 ;
        RECT 7.020 322.180 656.300 343.280 ;
        RECT 7.020 292.180 656.300 313.280 ;
        RECT 7.020 262.180 656.300 283.280 ;
        RECT 7.020 232.180 656.300 253.280 ;
        RECT 7.020 202.180 656.300 223.280 ;
        RECT 7.020 172.180 656.300 193.280 ;
        RECT 7.020 142.180 656.300 163.280 ;
        RECT 7.020 112.180 656.300 133.280 ;
        RECT 7.020 82.180 656.300 103.280 ;
        RECT 7.020 52.180 656.300 73.280 ;
        RECT 7.020 22.180 656.300 43.280 ;
        RECT 7.020 4.300 656.300 13.280 ;
  END
END aes_core
END LIBRARY

